FUNCTION "FC_GRP_80_R30" : VOID
TITLE =GROUP =80
{ S7_language := '9(1) Angielski (Stany Zjednoczone)  11.01.2022  09:45:15' }
VERSION : 0.1


VAR_TEMP
  CL : "UDT_CABINET";	//CABINET LOCAL
  CR : "UDT_CABINET";	//CABINET REMOTE
  RelError : BOOL ;	//ERROR RELEASE
  RelErrorCL : BOOL ;	//ERROR RELEASE FROM CABINET LOCAL
  RelErrorCR : BOOL ;	//ERROR RELEASE FROM CABINET REMOTE
  RelControl : BOOL ;	//CONTROL RELEASE
  RelControlCL : BOOL ;	//CONTROL RELEASE FROM CABINET LOCAL
  RelControlCR : BOOL ;	//CONTROL RELEASE FROM CABINET REMOTE
  ErrorConfirm : BOOL ;	//ERROR CONFIRM
  AutoOn : BOOL ;	//AUTOMATIC ON
  AutoOff : BOOL ;	//AUTOMATIC OFF
  RelAuto : BOOL ;	//AUTOMATIC RELEASE
  LAMP_ON : BOOL ;
  Safety_Brn71 : BOOL ;
  Safety_Brn72 : BOOL ;
  TempSetpoint : WORD ;
  Runtime_DI : DINT ;
  Runtime_R : REAL ;
  LS_BURNER_1 : BOOL ;
  LS_BURNER_2 : BOOL ;
END_VAR
BEGIN
NETWORK
TITLE =GLOBAL SIGNALS

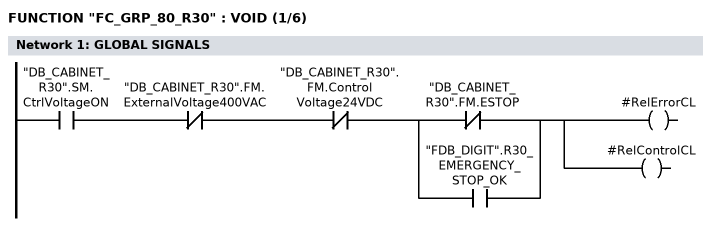
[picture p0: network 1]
      U     "DB_CABINET_R30".SM.CtrlVoltageON;
      UN    "DB_CABINET_R30".FM.ExternalVoltage400VAC;
      UN    "DB_CABINET_R30".FM.ControlVoltage24VDC;
      U(    ;
      ON    "DB_CABINET_R30".FM.ESTOP;
      O     "FDB_DIGIT".R30_EMERGENCY_STOP_OK;
      )     ;
      =     #RelErrorCL;
      =     #RelControlCL;
NETWORK
TITLE =GLOBAL SIGNALS



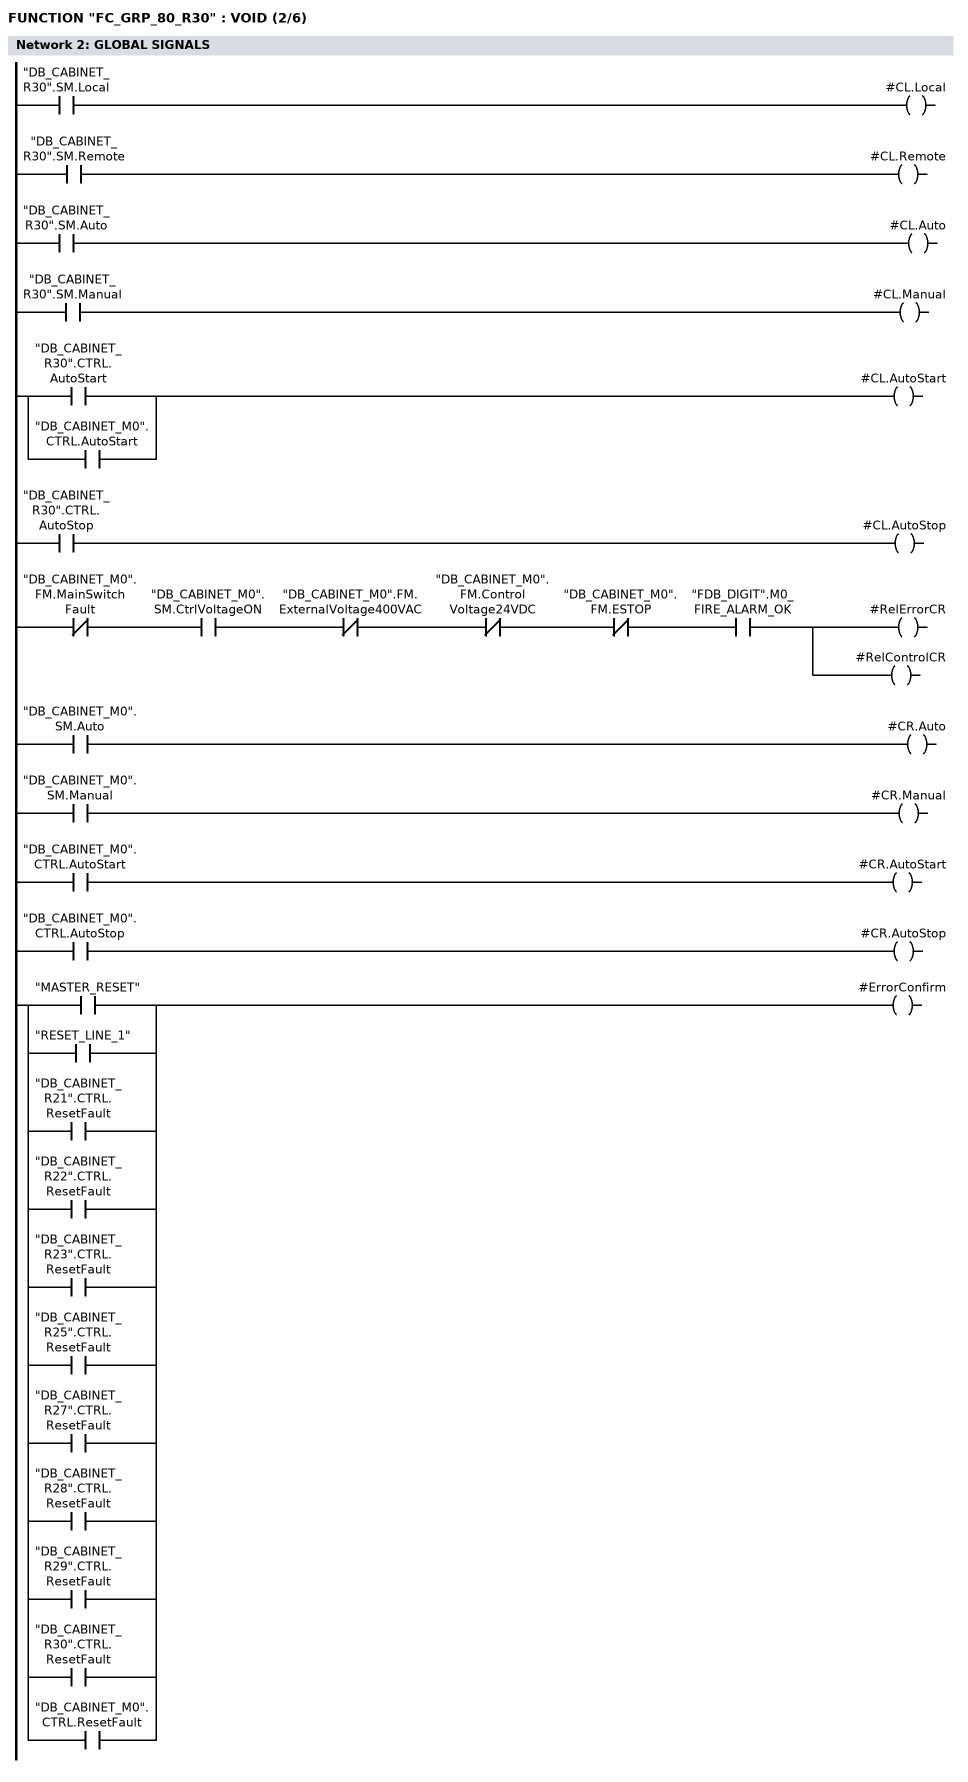
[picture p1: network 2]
      U     "DB_CABINET_R30".SM.Local;
      =     #CL.Local;
      U     "DB_CABINET_R30".SM.Remote;
      =     #CL.Remote;
      U     "DB_CABINET_R30".SM.Auto;
      =     #CL.Auto;
      U     "DB_CABINET_R30".SM.Manual;
      =     #CL.Manual;
      U     "DB_CABINET_R30".CTRL.AutoStart;
      O     "DB_CABINET_M0".CTRL.AutoStart;
      =     #CL.AutoStart;
      U     "DB_CABINET_R30".CTRL.AutoStop;
      =     #CL.AutoStop;


//REMOTE
      UN    "DB_CABINET_M0".FM.MainSwitchFault;
      U     "DB_CABINET_M0".SM.CtrlVoltageON;
      UN    "DB_CABINET_M0".FM.ExternalVoltage400VAC;
      UN    "DB_CABINET_M0".FM.ControlVoltage24VDC;
      UN    "DB_CABINET_M0".FM.ESTOP;
      U     "FDB_DIGIT".M0_FIRE_ALARM_OK;
      =     #RelErrorCR;
      =     #RelControlCR;

      U     "DB_CABINET_M0".SM.Auto;
      =     #CR.Auto;
      U     "DB_CABINET_M0".SM.Manual;
      =     #CR.Manual;
      U     "DB_CABINET_M0".CTRL.AutoStart;
      =     #CR.AutoStart;
      U     "DB_CABINET_M0".CTRL.AutoStop;
      =     #CR.AutoStop;

// Reset Alarms
      U     "MASTER_RESET";
      O     "RESET_LINE_1";
      O     "DB_CABINET_R21".CTRL.ResetFault;
      O     "DB_CABINET_R22".CTRL.ResetFault;
      O     "DB_CABINET_R23".CTRL.ResetFault;
      O     "DB_CABINET_R25".CTRL.ResetFault;
      O     "DB_CABINET_R27".CTRL.ResetFault;
      O     "DB_CABINET_R28".CTRL.ResetFault;
      O     "DB_CABINET_R29".CTRL.ResetFault;
      O     "DB_CABINET_R30".CTRL.ResetFault;
      O     "DB_CABINET_M0".CTRL.ResetFault;
      =     #ErrorConfirm;

NETWORK
TITLE =GLOBAL SIGNALS - GROUP GENERAL ERROR AND WARNING


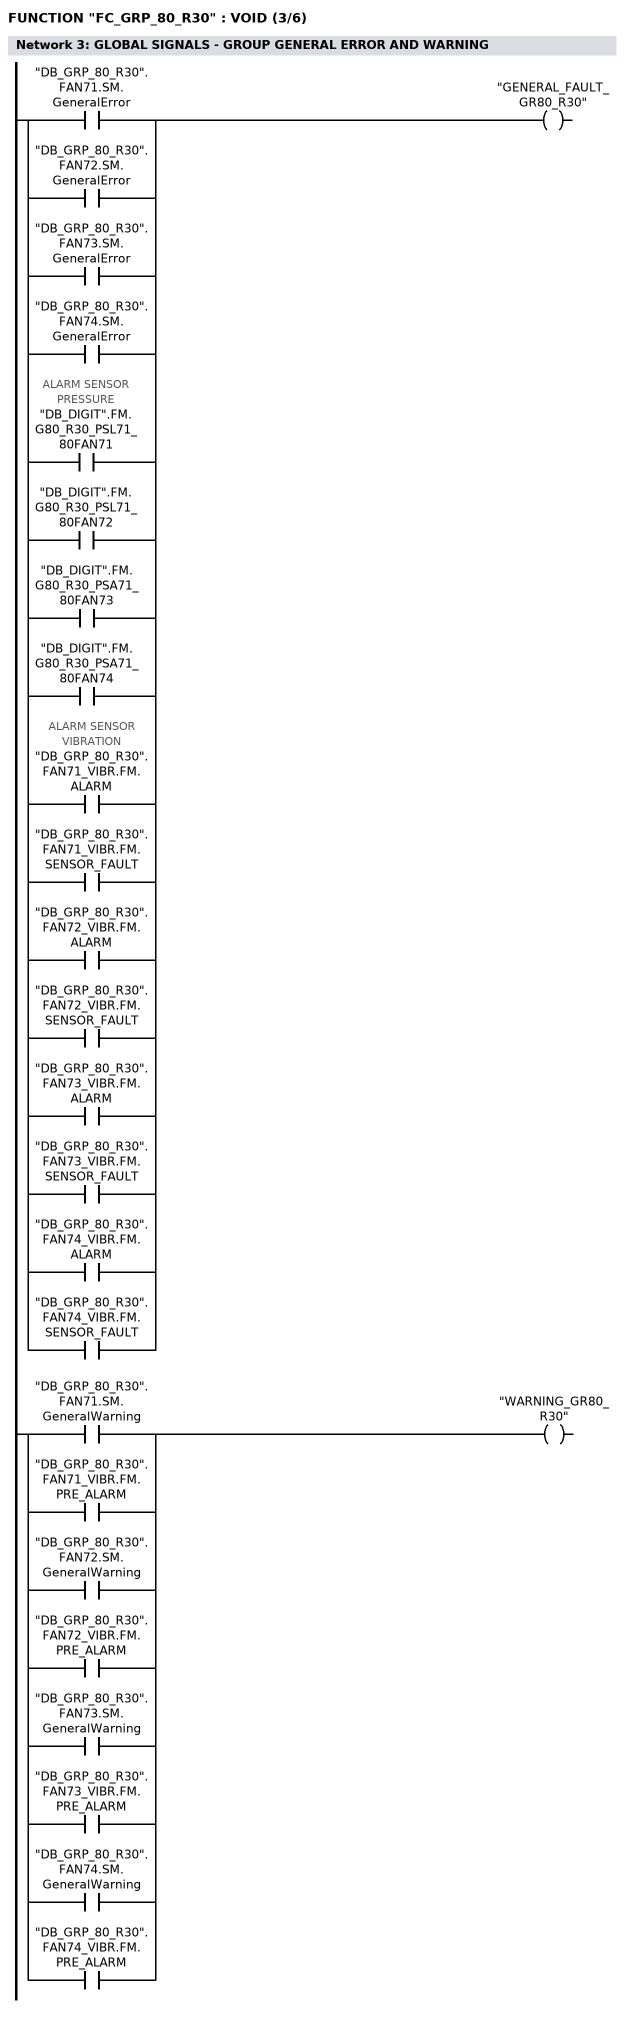
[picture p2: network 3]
      U     "DB_GRP_80_R30".FAN71.SM.GeneralError;
      O     "DB_GRP_80_R30".FAN72.SM.GeneralError;
      O     "DB_GRP_80_R30".FAN73.SM.GeneralError;
      O     "DB_GRP_80_R30".FAN74.SM.GeneralError;

      O     "DB_DIGIT".FM.G80_R30_PSL71_80FAN71; //ALARM SENSOR PRESSURE
      O     "DB_DIGIT".FM.G80_R30_PSL71_80FAN72;
      O     "DB_DIGIT".FM.G80_R30_PSA71_80FAN73;
      O     "DB_DIGIT".FM.G80_R30_PSA71_80FAN74;

      O     "DB_GRP_80_R30".FAN71_VIBR.FM.ALARM; //ALARM SENSOR VIBRATION
      O     "DB_GRP_80_R30".FAN71_VIBR.FM.SENSOR_FAULT;
      O     "DB_GRP_80_R30".FAN72_VIBR.FM.ALARM;
      O     "DB_GRP_80_R30".FAN72_VIBR.FM.SENSOR_FAULT;
      O     "DB_GRP_80_R30".FAN73_VIBR.FM.ALARM;
      O     "DB_GRP_80_R30".FAN73_VIBR.FM.SENSOR_FAULT;
      O     "DB_GRP_80_R30".FAN74_VIBR.FM.ALARM;
      O     "DB_GRP_80_R30".FAN74_VIBR.FM.SENSOR_FAULT;
      =     "GENERAL_FAULT_GR80_R30";

      U     "DB_GRP_80_R30".FAN71.SM.GeneralWarning;
      O     "DB_GRP_80_R30".FAN71_VIBR.FM.PRE_ALARM;
      O     "DB_GRP_80_R30".FAN72.SM.GeneralWarning;
      O     "DB_GRP_80_R30".FAN72_VIBR.FM.PRE_ALARM;
      O     "DB_GRP_80_R30".FAN73.SM.GeneralWarning;
      O     "DB_GRP_80_R30".FAN73_VIBR.FM.PRE_ALARM;
      O     "DB_GRP_80_R30".FAN74.SM.GeneralWarning;
      O     "DB_GRP_80_R30".FAN74_VIBR.FM.PRE_ALARM;
      =     "WARNING_GR80_R30";

NETWORK
TITLE =



NETWORK
TITLE =GENERAL ERROR RELEASE

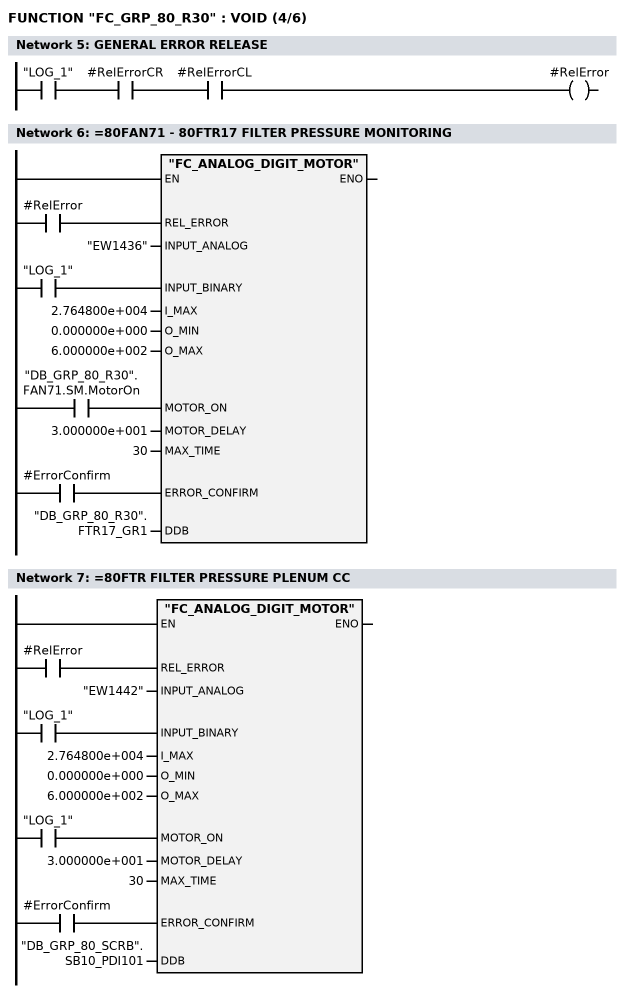
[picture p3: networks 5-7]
      U     "LOG_1";
      U     #RelErrorCR;
      U     #RelErrorCL;
      =     #RelError;
NETWORK
TITLE ==80FAN71 - 80FTR17 FILTER PRESSURE MONITORING

      U     #RelError;
      =     L     17.0;
      BLD   103;
      U     "LOG_1";
      =     L     17.1;
      BLD   103;
      U     "DB_GRP_80_R30".FAN71.SM.MotorOn;
      =     L     17.2;
      BLD   103;
      U     #ErrorConfirm;
      =     L     17.3;
      BLD   103;
      CALL "FC_ANALOG_DIGIT_MOTOR" (
           REL_ERROR                := L     17.0,
           INPUT_ANALOG             := "EW1436",
           INPUT_BINARY             := L     17.1,
           I_MAX                    := 2.764800e+004,
           O_MIN                    := 0.000000e+000,
           O_MAX                    := 6.000000e+002,
           MOTOR_ON                 := L     17.2,
           MOTOR_DELAY              := 3.000000e+001,
           MAX_TIME                 := 30,
           ERROR_CONFIRM            := L     17.3,
           DDB                      := "DB_GRP_80_R30".FTR17_GR1);
      NOP   0;
NETWORK
TITLE ==80FTR FILTER PRESSURE PLENUM CC

      U     #RelError;
      =     L     17.0;
      BLD   103;
      U     "LOG_1";
      =     L     17.1;
      BLD   103;
      U     "LOG_1";
      =     L     17.2;
      BLD   103;
      U     #ErrorConfirm;
      =     L     17.3;
      BLD   103;
      CALL "FC_ANALOG_DIGIT_MOTOR" (
           REL_ERROR                := L     17.0,
           INPUT_ANALOG             := "EW1442",
           INPUT_BINARY             := L     17.1,
           I_MAX                    := 2.764800e+004,
           O_MIN                    := 0.000000e+000,
           O_MAX                    := 6.000000e+002,
           MOTOR_ON                 := L     17.2,
           MOTOR_DELAY              := 3.000000e+001,
           MAX_TIME                 := 30,
           ERROR_CONFIRM            := L     17.3,
           DDB                      := "DB_GRP_80_SCRB".SB10_PDI101);
      NOP   0;
NETWORK
TITLE ==80FAN72 - 80FTR27 FILTER PRESSURE MONITORING

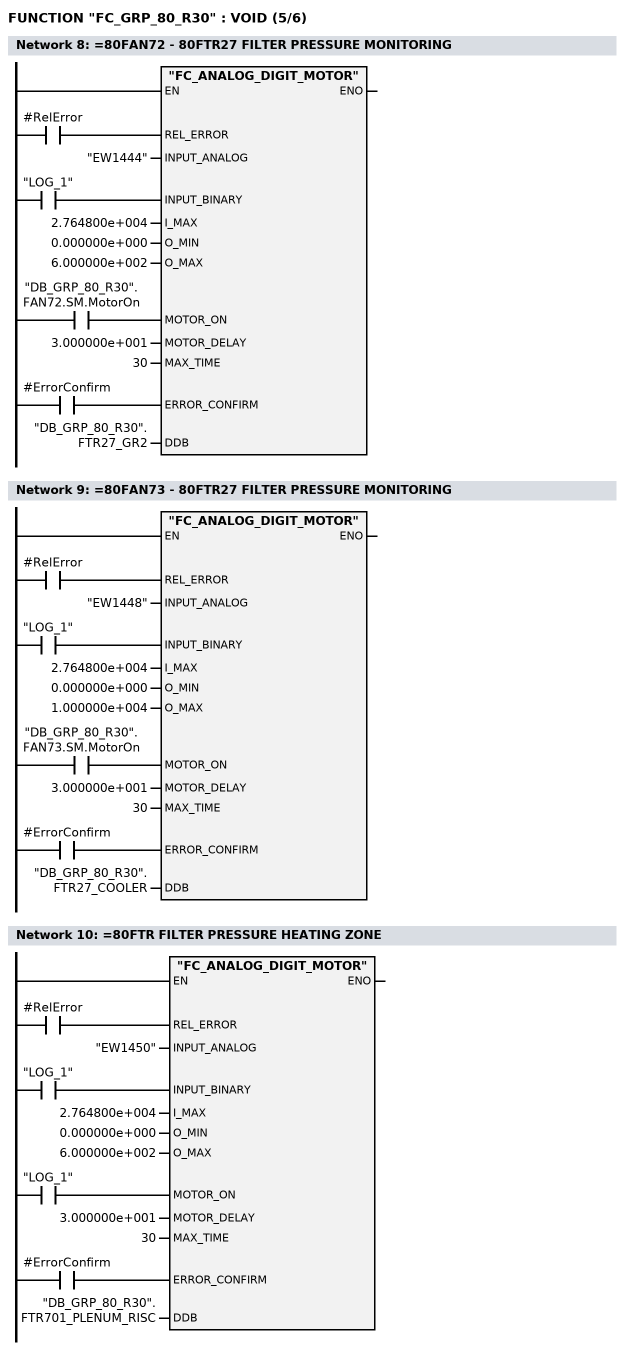
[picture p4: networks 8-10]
      U     #RelError;
      =     L     17.0;
      BLD   103;
      U     "LOG_1";
      =     L     17.1;
      BLD   103;
      U     "DB_GRP_80_R30".FAN72.SM.MotorOn;
      =     L     17.2;
      BLD   103;
      U     #ErrorConfirm;
      =     L     17.3;
      BLD   103;
      CALL "FC_ANALOG_DIGIT_MOTOR" (
           REL_ERROR                := L     17.0,
           INPUT_ANALOG             := "EW1444",
           INPUT_BINARY             := L     17.1,
           I_MAX                    := 2.764800e+004,
           O_MIN                    := 0.000000e+000,
           O_MAX                    := 6.000000e+002,
           MOTOR_ON                 := L     17.2,
           MOTOR_DELAY              := 3.000000e+001,
           MAX_TIME                 := 30,
           ERROR_CONFIRM            := L     17.3,
           DDB                      := "DB_GRP_80_R30".FTR27_GR2);
      NOP   0;
NETWORK
TITLE ==80FAN73 - 80FTR27 FILTER PRESSURE MONITORING

      U     #RelError;
      =     L     17.0;
      BLD   103;
      U     "LOG_1";
      =     L     17.1;
      BLD   103;
      U     "DB_GRP_80_R30".FAN73.SM.MotorOn;
      =     L     17.2;
      BLD   103;
      U     #ErrorConfirm;
      =     L     17.3;
      BLD   103;
      CALL "FC_ANALOG_DIGIT_MOTOR" (
           REL_ERROR                := L     17.0,
           INPUT_ANALOG             := "EW1448",
           INPUT_BINARY             := L     17.1,
           I_MAX                    := 2.764800e+004,
           O_MIN                    := 0.000000e+000,
           O_MAX                    := 1.000000e+004,
           MOTOR_ON                 := L     17.2,
           MOTOR_DELAY              := 3.000000e+001,
           MAX_TIME                 := 30,
           ERROR_CONFIRM            := L     17.3,
           DDB                      := "DB_GRP_80_R30".FTR27_COOLER);
      NOP   0;
NETWORK
TITLE ==80FTR FILTER PRESSURE HEATING ZONE

      U     #RelError;
      =     L     17.0;
      BLD   103;
      U     "LOG_1";
      =     L     17.1;
      BLD   103;
      U     "LOG_1";
      =     L     17.2;
      BLD   103;
      U     #ErrorConfirm;
      =     L     17.3;
      BLD   103;
      CALL "FC_ANALOG_DIGIT_MOTOR" (
           REL_ERROR                := L     17.0,
           INPUT_ANALOG             := "EW1450",
           INPUT_BINARY             := L     17.1,
           I_MAX                    := 2.764800e+004,
           O_MIN                    := 0.000000e+000,
           O_MAX                    := 6.000000e+002,
           MOTOR_ON                 := L     17.2,
           MOTOR_DELAY              := 3.000000e+001,
           MAX_TIME                 := 30,
           ERROR_CONFIRM            := L     17.3,
           DDB                      := "DB_GRP_80_R30".FTR701_PLENUM_RISC);
      NOP   0;
NETWORK
TITLE ==80FTR FILTER PRESSURE COOLING ZONE

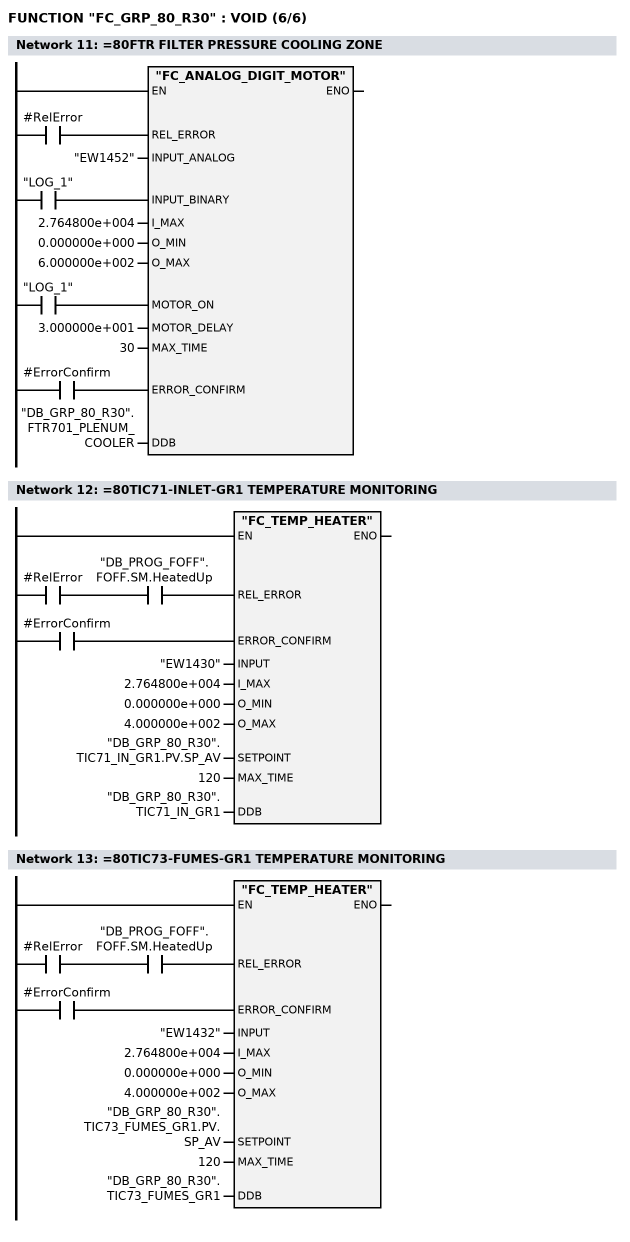
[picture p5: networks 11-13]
      U     #RelError;
      =     L     17.0;
      BLD   103;
      U     "LOG_1";
      =     L     17.1;
      BLD   103;
      U     "LOG_1";
      =     L     17.2;
      BLD   103;
      U     #ErrorConfirm;
      =     L     17.3;
      BLD   103;
      CALL "FC_ANALOG_DIGIT_MOTOR" (
           REL_ERROR                := L     17.0,
           INPUT_ANALOG             := "EW1452",
           INPUT_BINARY             := L     17.1,
           I_MAX                    := 2.764800e+004,
           O_MIN                    := 0.000000e+000,
           O_MAX                    := 6.000000e+002,
           MOTOR_ON                 := L     17.2,
           MOTOR_DELAY              := 3.000000e+001,
           MAX_TIME                 := 30,
           ERROR_CONFIRM            := L     17.3,
           DDB                      := "DB_GRP_80_R30".FTR701_PLENUM_COOLER);
      NOP   0;
NETWORK
TITLE ==80TIC71-INLET-GR1 TEMPERATURE MONITORING

      U     #RelError;
      U     "DB_PROG_FOFF".FOFF.SM.HeatedUp;
      =     L     17.0;
      BLD   103;
      U     #ErrorConfirm;
      =     L     17.1;
      BLD   103;
      CALL "FC_TEMP_HEATER" (
           REL_ERROR                := L     17.0,
           ERROR_CONFIRM            := L     17.1,
           INPUT                    := "EW1430",
           I_MAX                    := 2.764800e+004,
           O_MIN                    := 0.000000e+000,
           O_MAX                    := 4.000000e+002,
           SETPOINT                 := "DB_GRP_80_R30".TIC71_IN_GR1.PV.SP_AV,
           MAX_TIME                 := 120,
           DDB                      := "DB_GRP_80_R30".TIC71_IN_GR1);
      NOP   0;
NETWORK
TITLE ==80TIC73-FUMES-GR1 TEMPERATURE MONITORING

      U     #RelError;
      U     "DB_PROG_FOFF".FOFF.SM.HeatedUp;
      =     L     17.0;
      BLD   103;
      U     #ErrorConfirm;
      =     L     17.1;
      BLD   103;
      CALL "FC_TEMP_HEATER" (
           REL_ERROR                := L     17.0,
           ERROR_CONFIRM            := L     17.1,
           INPUT                    := "EW1432",
           I_MAX                    := 2.764800e+004,
           O_MIN                    := 0.000000e+000,
           O_MAX                    := 4.000000e+002,
           SETPOINT                 := "DB_GRP_80_R30".TIC73_FUMES_GR1.PV.SP_AV,
           MAX_TIME                 := 120,
           DDB                      := "DB_GRP_80_R30".TIC73_FUMES_GR1);
      NOP   0;
NETWORK
TITLE ==80TIC71-RETURN-GR1 TEMPERATURE MONITORING


      L     "EW1454";
      L     0;
      >=I   ;
      SPB   M014;
      L     0.000000e+000;
      SPA   M015;
M014: L     "EW1454";
      ITD   ;
      DTR   ;
      L     1.000000e+001;
      /R    ;
M015: T     "DB_GRP_80_R30".TIC71_RET_GR1.PV.AV;

NETWORK
TITLE ==80TIC71-INLET-GR2 TEMPERATURE MONITORING

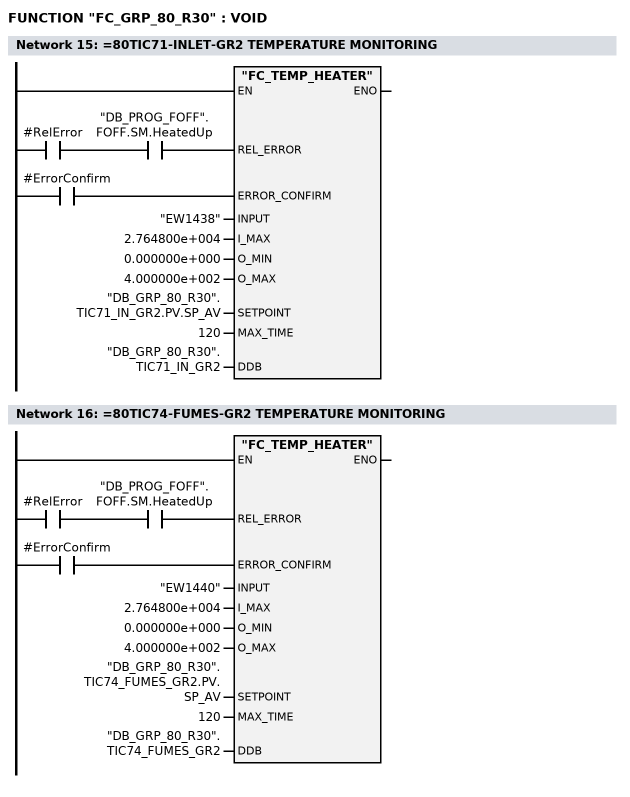
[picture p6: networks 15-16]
      U     #RelError;
      U     "DB_PROG_FOFF".FOFF.SM.HeatedUp;
      =     L     17.0;
      BLD   103;
      U     #ErrorConfirm;
      =     L     17.1;
      BLD   103;
      CALL "FC_TEMP_HEATER" (
           REL_ERROR                := L     17.0,
           ERROR_CONFIRM            := L     17.1,
           INPUT                    := "EW1438",
           I_MAX                    := 2.764800e+004,
           O_MIN                    := 0.000000e+000,
           O_MAX                    := 4.000000e+002,
           SETPOINT                 := "DB_GRP_80_R30".TIC71_IN_GR2.PV.SP_AV,
           MAX_TIME                 := 120,
           DDB                      := "DB_GRP_80_R30".TIC71_IN_GR2);
      NOP   0;
NETWORK
TITLE ==80TIC74-FUMES-GR2 TEMPERATURE MONITORING

      U     #RelError;
      U     "DB_PROG_FOFF".FOFF.SM.HeatedUp;
      =     L     17.0;
      BLD   103;
      U     #ErrorConfirm;
      =     L     17.1;
      BLD   103;
      CALL "FC_TEMP_HEATER" (
           REL_ERROR                := L     17.0,
           ERROR_CONFIRM            := L     17.1,
           INPUT                    := "EW1440",
           I_MAX                    := 2.764800e+004,
           O_MIN                    := 0.000000e+000,
           O_MAX                    := 4.000000e+002,
           SETPOINT                 := "DB_GRP_80_R30".TIC74_FUMES_GR2.PV.SP_AV,
           MAX_TIME                 := 120,
           DDB                      := "DB_GRP_80_R30".TIC74_FUMES_GR2);
      NOP   0;
NETWORK
TITLE ==80TIC72-RETURN-GR2 TEMPERATURE MONITORING


      L     "EW1456";
      L     0;
      >=I   ;
      SPB   M016;
      L     0.000000e+000;
      SPA   M017;
M016: L     "EW1456";
      ITD   ;
      DTR   ;
      L     1.000000e+001;
      /R    ;
M017: T     "DB_GRP_80_R30".TIC72_RET_GR2.PV.AV;

NETWORK
TITLE =



NETWORK
TITLE ==80TIC75-COOLING TEMPERATURE MONITORING

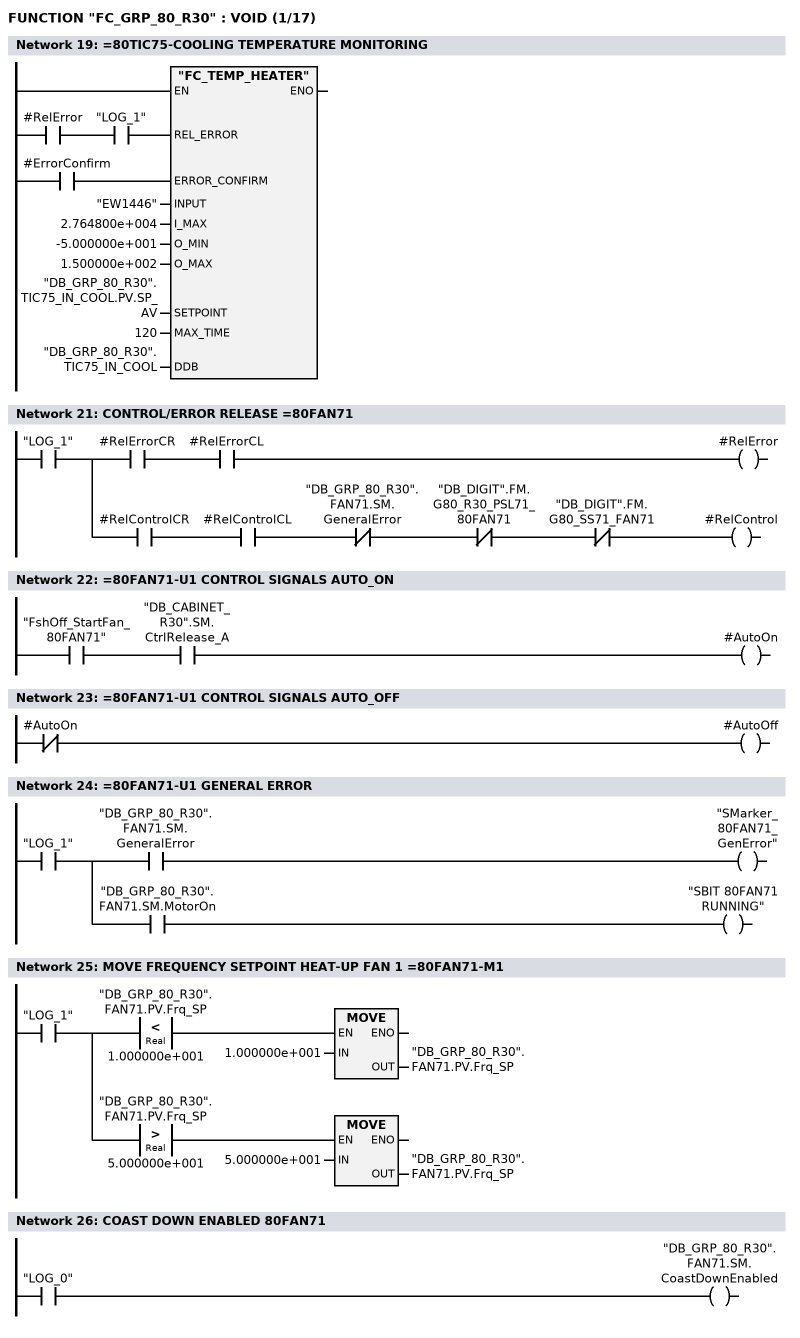
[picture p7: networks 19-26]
      U     #RelError;
      U     "LOG_1";
      =     L     17.0;
      BLD   103;
      U     #ErrorConfirm;
      =     L     17.1;
      BLD   103;
      CALL "FC_TEMP_HEATER" (
           REL_ERROR                := L     17.0,
           ERROR_CONFIRM            := L     17.1,
           INPUT                    := "EW1446",
           I_MAX                    := 2.764800e+004,
           O_MIN                    := -5.000000e+001,
           O_MAX                    := 1.500000e+002,
           SETPOINT                 := "DB_GRP_80_R30".TIC75_IN_COOL.PV.SP_AV,
           MAX_TIME                 := 120,
           DDB                      := "DB_GRP_80_R30".TIC75_IN_COOL);
      NOP   0;
NETWORK
TITLE =



NETWORK
TITLE =CONTROL/ERROR RELEASE =80FAN71

      U     "LOG_1";
      =     L     17.0;
      U     L     17.0;
      U     #RelErrorCR;
      U     #RelErrorCL;
      =     #RelError;
      U     L     17.0;
      U     #RelControlCR;
      U     #RelControlCL;
      UN    "DB_GRP_80_R30".FAN71.SM.GeneralError;
      UN    "DB_DIGIT".FM.G80_R30_PSL71_80FAN71;
      UN    "DB_DIGIT".FM.G80_SS71_FAN71;
      =     #RelControl;
NETWORK
TITLE ==80FAN71-U1 CONTROL SIGNALS AUTO_ON

      U     "FshOff_StartFan_80FAN71";
      U     "DB_CABINET_R30".SM.CtrlRelease_A;
      =     #AutoOn;
NETWORK
TITLE ==80FAN71-U1 CONTROL SIGNALS AUTO_OFF

      UN    #AutoOn;
      =     #AutoOff;
NETWORK
TITLE ==80FAN71-U1 GENERAL ERROR

      U     "LOG_1";
      =     L     17.0;
      U     L     17.0;
      U     "DB_GRP_80_R30".FAN71.SM.GeneralError;
      =     "SMarker_80FAN71_GenError";
      U     L     17.0;
      U     "DB_GRP_80_R30".FAN71.SM.MotorOn;
      =     "SBIT 80FAN71 RUNNING";
NETWORK
TITLE =MOVE FREQUENCY SETPOINT HEAT-UP FAN 1 =80FAN71-M1

      U     "LOG_1";
      =     L     17.0;
      U     L     17.0;
      U(    ;
      L     "DB_GRP_80_R30".FAN71.PV.Frq_SP;
      L     1.000000e+001;
      <R    ;
      )     ;
      SPBNB _001;
      L     1.000000e+001;
      T     "DB_GRP_80_R30".FAN71.PV.Frq_SP;
_001: NOP   0;
      U     L     17.0;
      U(    ;
      L     "DB_GRP_80_R30".FAN71.PV.Frq_SP;
      L     5.000000e+001;
      >R    ;
      )     ;
      SPBNB _002;
      L     5.000000e+001;
      T     "DB_GRP_80_R30".FAN71.PV.Frq_SP;
_002: NOP   0;
NETWORK
TITLE =COAST DOWN ENABLED 80FAN71

      U     "LOG_0";
      =     "DB_GRP_80_R30".FAN71.SM.CoastDownEnabled;
NETWORK
TITLE ==80FAN71-U1 HEAT-UP FAN

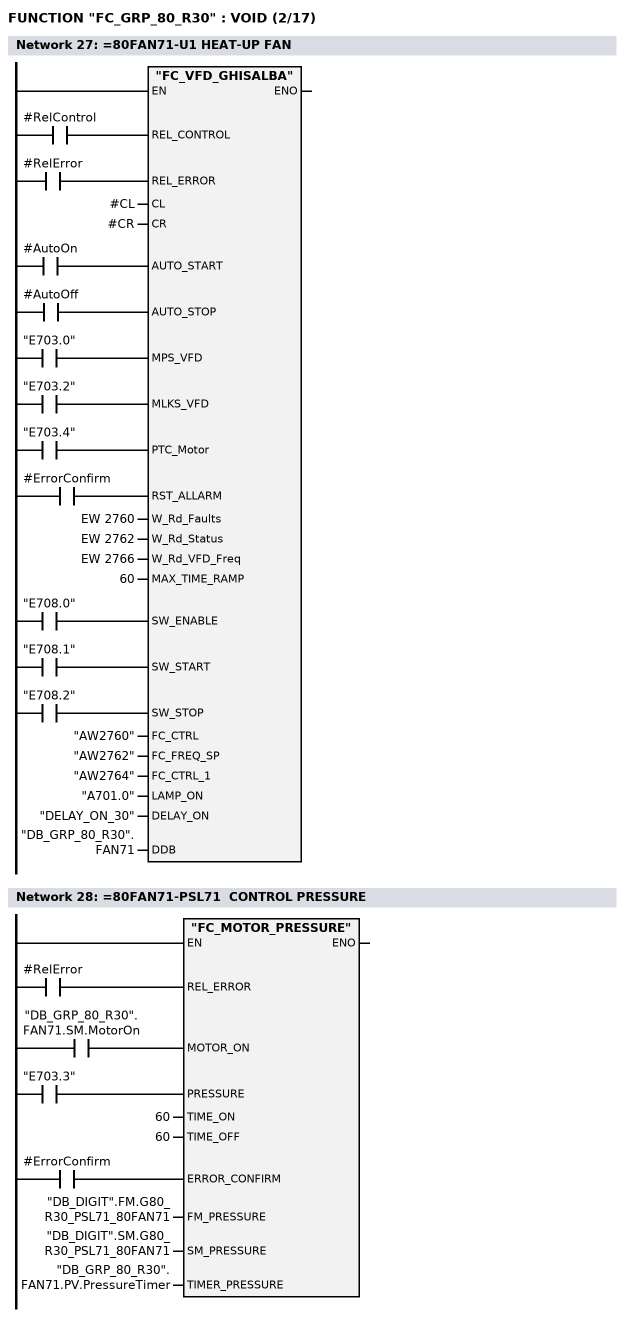
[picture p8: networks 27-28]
      U     #RelControl;
      =     L     17.0;
      BLD   103;
      U     #RelError;
      =     L     17.1;
      BLD   103;
      U     #AutoOn;
      =     L     17.2;
      BLD   103;
      U     #AutoOff;
      =     L     17.3;
      BLD   103;
      U     "E703.0";
      =     L     17.4;
      BLD   103;
      U     "E703.2";
      =     L     17.5;
      BLD   103;
      U     "E703.4";
      =     L     17.6;
      BLD   103;
      U     #ErrorConfirm;
      =     L     17.7;
      BLD   103;
      U     "E708.0";
      =     L     18.0;
      BLD   103;
      U     "E708.1";
      =     L     18.1;
      BLD   103;
      U     "E708.2";
      =     L     18.2;
      BLD   103;
      CALL "FC_VFD_GHISALBA" (
           REL_CONTROL              := L     17.0,
           REL_ERROR                := L     17.1,
           CL                       := #CL,
           CR                       := #CR,
           AUTO_START               := L     17.2,
           AUTO_STOP                := L     17.3,
           MPS_VFD                  := L     17.4,
           MLKS_VFD                 := L     17.5,
           PTC_Motor                := L     17.6,
           RST_ALLARM               := L     17.7,
           W_Rd_Faults              := EW  2760,
           W_Rd_Status              := EW  2762,
           W_Rd_VFD_Freq            := EW  2766,
           MAX_TIME_RAMP            := 60,
           SW_ENABLE                := L     18.0,
           SW_START                 := L     18.1,
           SW_STOP                  := L     18.2,
           FC_CTRL                  := "AW2760",
           FC_FREQ_SP               := "AW2762",
           FC_CTRL_1                := "AW2764",
           LAMP_ON                  := "A701.0",
           DELAY_ON                 := "DELAY_ON_30",
           DDB                      := "DB_GRP_80_R30".FAN71);
      NOP   0;
NETWORK
TITLE ==80FAN71-PSL71  CONTROL PRESSURE

      U     #RelError;
      =     L     17.0;
      BLD   103;
      U     "DB_GRP_80_R30".FAN71.SM.MotorOn;
      =     L     17.1;
      BLD   103;
      U     "E703.3";
      =     L     17.2;
      BLD   103;
      U     #ErrorConfirm;
      =     L     17.3;
      BLD   103;
      CALL "FC_MOTOR_PRESSURE" (
           REL_ERROR                := L     17.0,
           MOTOR_ON                 := L     17.1,
           PRESSURE                 := L     17.2,
           TIME_ON                  := 60,
           TIME_OFF                 := 60,
           ERROR_CONFIRM            := L     17.3,
           FM_PRESSURE              := "DB_DIGIT".FM.G80_R30_PSL71_80FAN71,
           SM_PRESSURE              := "DB_DIGIT".SM.G80_R30_PSL71_80FAN71,
           TIMER_PRESSURE           := "DB_GRP_80_R30".FAN71.PV.PressureTimer);
      NOP   0;
NETWORK
TITLE =VIBRATION SENSOR =80FAN71

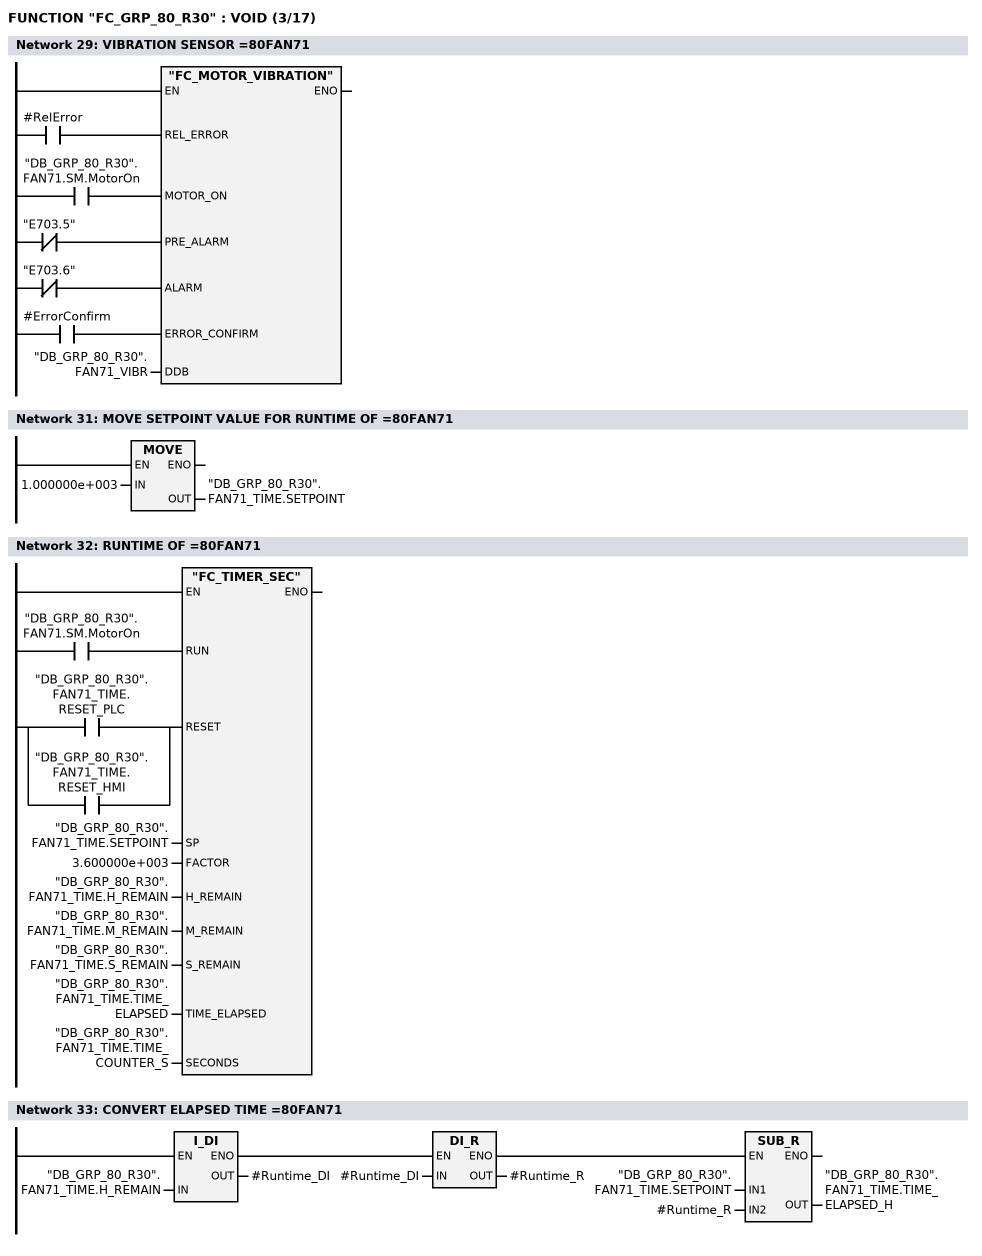
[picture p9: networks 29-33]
      U     #RelError;
      =     L     17.0;
      BLD   103;
      U     "DB_GRP_80_R30".FAN71.SM.MotorOn;
      =     L     17.1;
      BLD   103;
      UN    "E703.5";
      =     L     17.2;
      BLD   103;
      UN    "E703.6";
      =     L     17.3;
      BLD   103;
      U     #ErrorConfirm;
      =     L     17.4;
      BLD   103;
      CALL "FC_MOTOR_VIBRATION" (
           REL_ERROR                := L     17.0,
           MOTOR_ON                 := L     17.1,
           PRE_ALARM                := L     17.2,
           ALARM                    := L     17.3,
           ERROR_CONFIRM            := L     17.4,
           DDB                      := "DB_GRP_80_R30".FAN71_VIBR);
      NOP   0;
NETWORK
TITLE =****** RUNTIME METER ********



NETWORK
TITLE =MOVE SETPOINT VALUE FOR RUNTIME OF =80FAN71

      L     1.000000e+003;
      T     "DB_GRP_80_R30".FAN71_TIME.SETPOINT;
      NOP   0;
NETWORK
TITLE =RUNTIME OF =80FAN71

      U     "DB_GRP_80_R30".FAN71.SM.MotorOn;
      =     L     17.0;
      BLD   103;
      U(    ;
      O     "DB_GRP_80_R30".FAN71_TIME.RESET_PLC;
      O     "DB_GRP_80_R30".FAN71_TIME.RESET_HMI;
      )     ;
      =     L     17.1;
      BLD   103;
      CALL "FC_TIMER_SEC" (
           RUN                      := L     17.0,
           RESET                    := L     17.1,
           SP                       := "DB_GRP_80_R30".FAN71_TIME.SETPOINT,
           FACTOR                   := 3.600000e+003,
           H_REMAIN                 := "DB_GRP_80_R30".FAN71_TIME.H_REMAIN,
           M_REMAIN                 := "DB_GRP_80_R30".FAN71_TIME.M_REMAIN,
           S_REMAIN                 := "DB_GRP_80_R30".FAN71_TIME.S_REMAIN,
           TIME_ELAPSED             := "DB_GRP_80_R30".FAN71_TIME.TIME_ELAPSED,
           SECONDS                  := "DB_GRP_80_R30".FAN71_TIME.TIME_COUNTER_S);
      NOP   0;
NETWORK
TITLE =CONVERT ELAPSED TIME =80FAN71

      U(    ;
      U(    ;
      L     "DB_GRP_80_R30".FAN71_TIME.H_REMAIN;
      ITD   ;
      T     #Runtime_DI;
      SET   ;
      SAVE  ;
      CLR   ;
      U     BIE;
      )     ;
      SPBNB _003;
      L     #Runtime_DI;
      DTR   ;
      T     #Runtime_R;
      SET   ;
      SAVE  ;
      CLR   ;
_003: U     BIE;
      )     ;
      SPBNB _004;
      L     "DB_GRP_80_R30".FAN71_TIME.SETPOINT;
      L     #Runtime_R;
      -R    ;
      T     "DB_GRP_80_R30".FAN71_TIME.TIME_ELAPSED_H;
_004: NOP   0;
NETWORK
TITLE =



NETWORK
TITLE =CONTROL/ERROR RELEASE =80FAN72

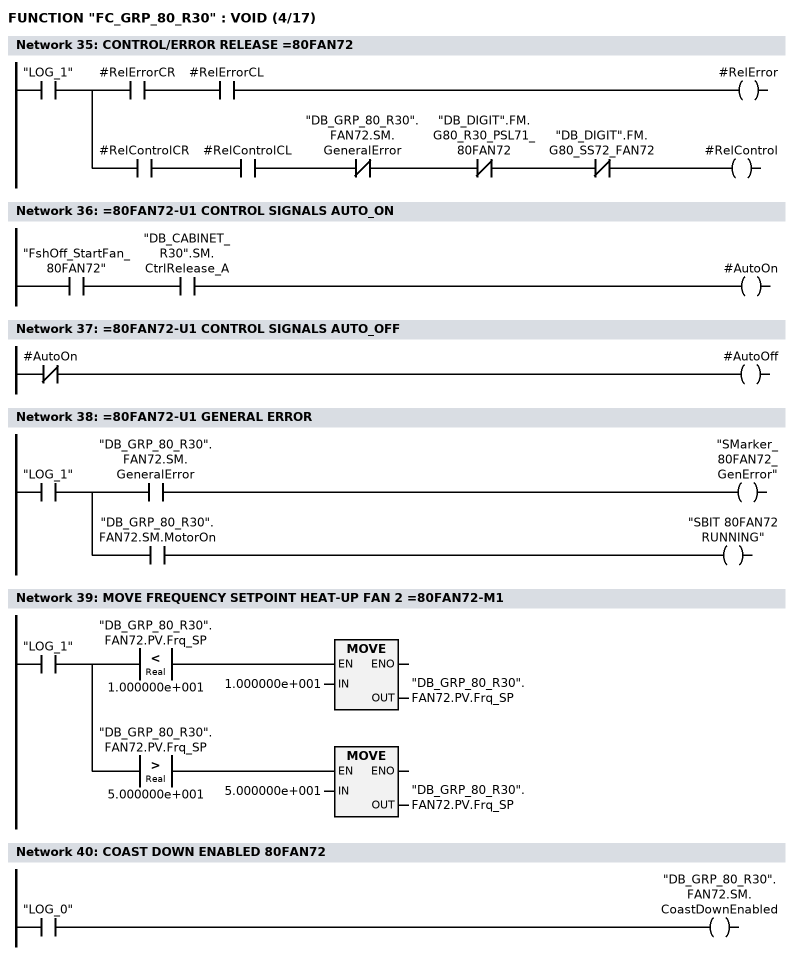
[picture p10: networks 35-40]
      U     "LOG_1";
      =     L     17.0;
      U     L     17.0;
      U     #RelErrorCR;
      U     #RelErrorCL;
      =     #RelError;
      U     L     17.0;
      U     #RelControlCR;
      U     #RelControlCL;
      UN    "DB_GRP_80_R30".FAN72.SM.GeneralError;
      UN    "DB_DIGIT".FM.G80_R30_PSL71_80FAN72;
      UN    "DB_DIGIT".FM.G80_SS72_FAN72;
      =     #RelControl;
NETWORK
TITLE ==80FAN72-U1 CONTROL SIGNALS AUTO_ON

      U     "FshOff_StartFan_80FAN72";
      U     "DB_CABINET_R30".SM.CtrlRelease_A;
      =     #AutoOn;
NETWORK
TITLE ==80FAN72-U1 CONTROL SIGNALS AUTO_OFF

      UN    #AutoOn;
      =     #AutoOff;
NETWORK
TITLE ==80FAN72-U1 GENERAL ERROR

      U     "LOG_1";
      =     L     17.0;
      U     L     17.0;
      U     "DB_GRP_80_R30".FAN72.SM.GeneralError;
      =     "SMarker_80FAN72_GenError";
      U     L     17.0;
      U     "DB_GRP_80_R30".FAN72.SM.MotorOn;
      =     "SBIT 80FAN72 RUNNING";
NETWORK
TITLE =MOVE FREQUENCY SETPOINT HEAT-UP FAN 2 =80FAN72-M1

      U     "LOG_1";
      =     L     17.0;
      U     L     17.0;
      U(    ;
      L     "DB_GRP_80_R30".FAN72.PV.Frq_SP;
      L     1.000000e+001;
      <R    ;
      )     ;
      SPBNB _005;
      L     1.000000e+001;
      T     "DB_GRP_80_R30".FAN72.PV.Frq_SP;
_005: NOP   0;
      U     L     17.0;
      U(    ;
      L     "DB_GRP_80_R30".FAN72.PV.Frq_SP;
      L     5.000000e+001;
      >R    ;
      )     ;
      SPBNB _006;
      L     5.000000e+001;
      T     "DB_GRP_80_R30".FAN72.PV.Frq_SP;
_006: NOP   0;
NETWORK
TITLE =COAST DOWN ENABLED 80FAN72

      U     "LOG_0";
      =     "DB_GRP_80_R30".FAN72.SM.CoastDownEnabled;
NETWORK
TITLE ==80FAN72-U1 HEATING GROUP AIR FAN 2

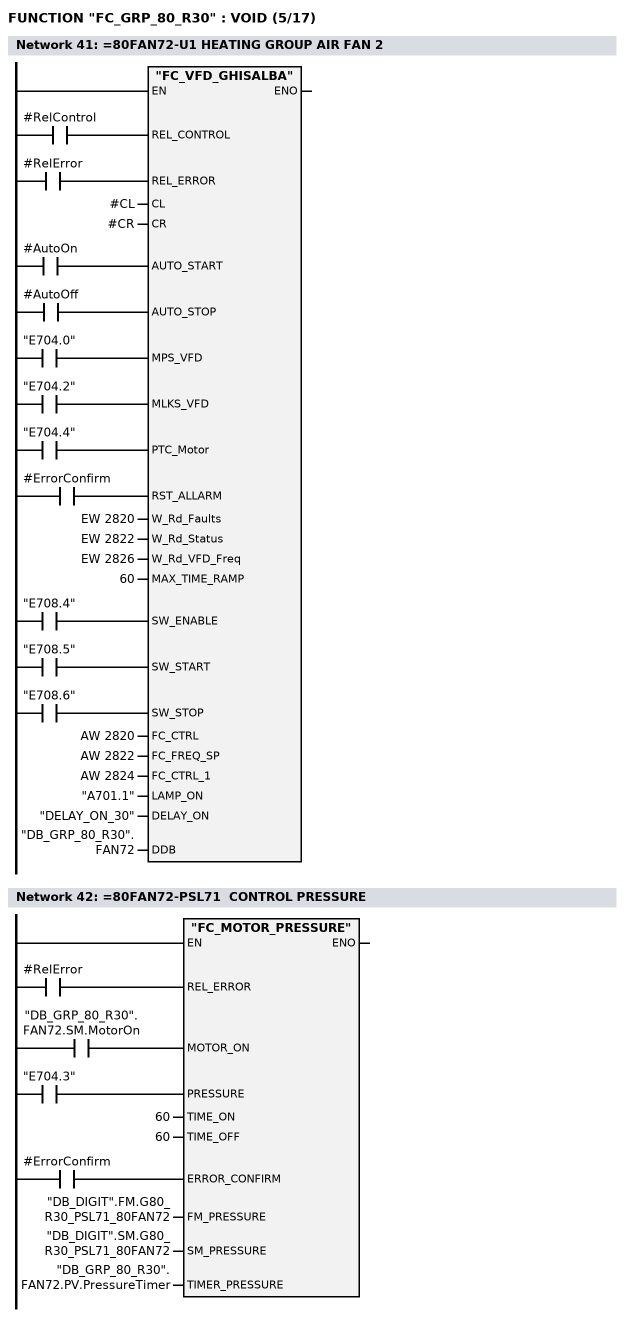
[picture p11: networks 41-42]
      U     #RelControl;
      =     L     17.0;
      BLD   103;
      U     #RelError;
      =     L     17.1;
      BLD   103;
      U     #AutoOn;
      =     L     17.2;
      BLD   103;
      U     #AutoOff;
      =     L     17.3;
      BLD   103;
      U     "E704.0";
      =     L     17.4;
      BLD   103;
      U     "E704.2";
      =     L     17.5;
      BLD   103;
      U     "E704.4";
      =     L     17.6;
      BLD   103;
      U     #ErrorConfirm;
      =     L     17.7;
      BLD   103;
      U     "E708.4";
      =     L     18.0;
      BLD   103;
      U     "E708.5";
      =     L     18.1;
      BLD   103;
      U     "E708.6";
      =     L     18.2;
      BLD   103;
      CALL "FC_VFD_GHISALBA" (
           REL_CONTROL              := L     17.0,
           REL_ERROR                := L     17.1,
           CL                       := #CL,
           CR                       := #CR,
           AUTO_START               := L     17.2,
           AUTO_STOP                := L     17.3,
           MPS_VFD                  := L     17.4,
           MLKS_VFD                 := L     17.5,
           PTC_Motor                := L     17.6,
           RST_ALLARM               := L     17.7,
           W_Rd_Faults              := EW  2820,
           W_Rd_Status              := EW  2822,
           W_Rd_VFD_Freq            := EW  2826,
           MAX_TIME_RAMP            := 60,
           SW_ENABLE                := L     18.0,
           SW_START                 := L     18.1,
           SW_STOP                  := L     18.2,
           FC_CTRL                  := AW  2820,
           FC_FREQ_SP               := AW  2822,
           FC_CTRL_1                := AW  2824,
           LAMP_ON                  := "A701.1",
           DELAY_ON                 := "DELAY_ON_30",
           DDB                      := "DB_GRP_80_R30".FAN72);
      NOP   0;
NETWORK
TITLE ==80FAN72-PSL71  CONTROL PRESSURE

      U     #RelError;
      =     L     17.0;
      BLD   103;
      U     "DB_GRP_80_R30".FAN72.SM.MotorOn;
      =     L     17.1;
      BLD   103;
      U     "E704.3";
      =     L     17.2;
      BLD   103;
      U     #ErrorConfirm;
      =     L     17.3;
      BLD   103;
      CALL "FC_MOTOR_PRESSURE" (
           REL_ERROR                := L     17.0,
           MOTOR_ON                 := L     17.1,
           PRESSURE                 := L     17.2,
           TIME_ON                  := 60,
           TIME_OFF                 := 60,
           ERROR_CONFIRM            := L     17.3,
           FM_PRESSURE              := "DB_DIGIT".FM.G80_R30_PSL71_80FAN72,
           SM_PRESSURE              := "DB_DIGIT".SM.G80_R30_PSL71_80FAN72,
           TIMER_PRESSURE           := "DB_GRP_80_R30".FAN72.PV.PressureTimer);
      NOP   0;
NETWORK
TITLE =VIBRATION SENSOR

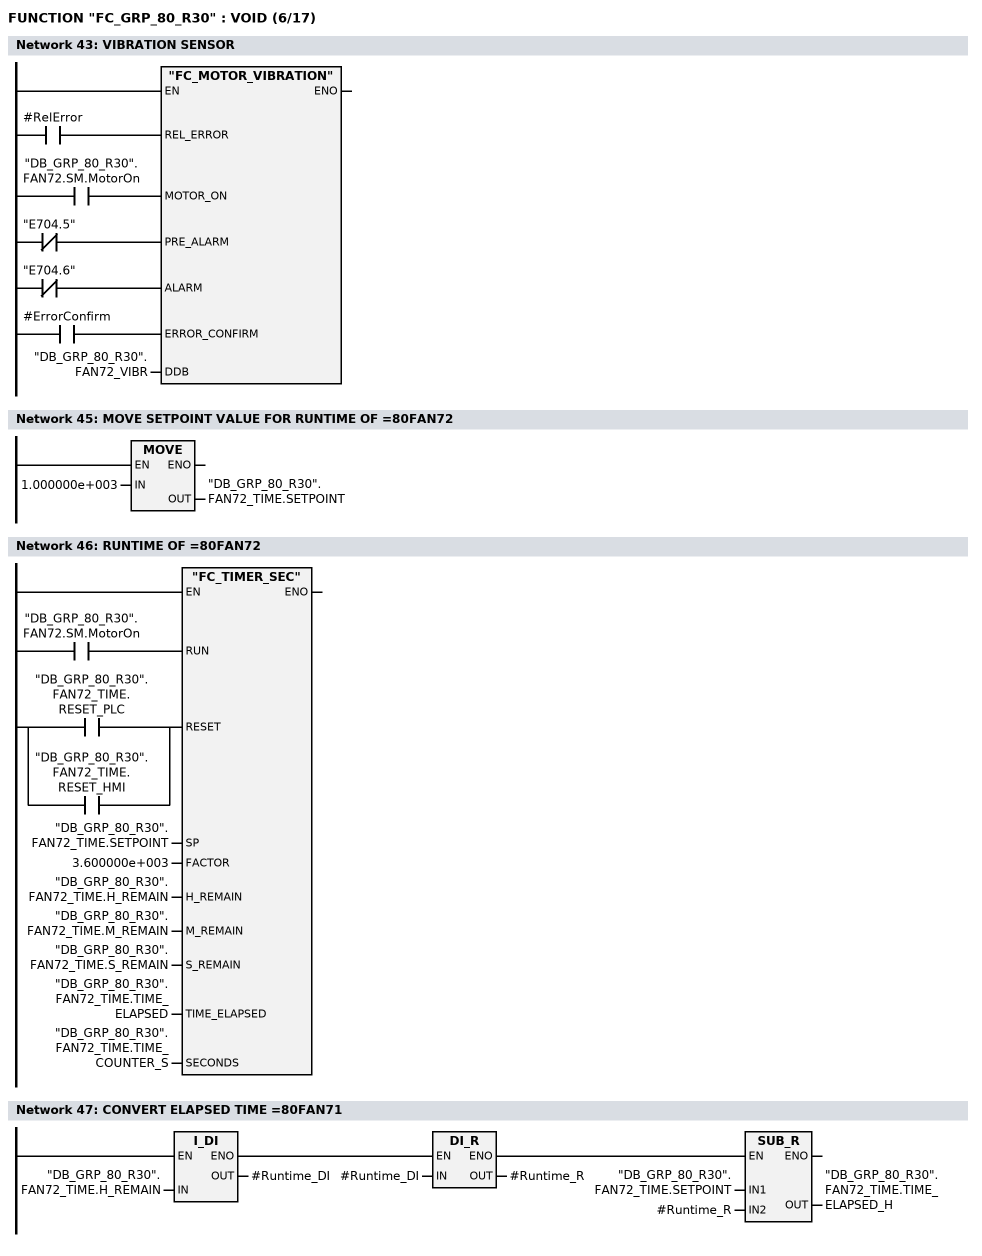
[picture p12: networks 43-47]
      U     #RelError;
      =     L     17.0;
      BLD   103;
      U     "DB_GRP_80_R30".FAN72.SM.MotorOn;
      =     L     17.1;
      BLD   103;
      UN    "E704.5";
      =     L     17.2;
      BLD   103;
      UN    "E704.6";
      =     L     17.3;
      BLD   103;
      U     #ErrorConfirm;
      =     L     17.4;
      BLD   103;
      CALL "FC_MOTOR_VIBRATION" (
           REL_ERROR                := L     17.0,
           MOTOR_ON                 := L     17.1,
           PRE_ALARM                := L     17.2,
           ALARM                    := L     17.3,
           ERROR_CONFIRM            := L     17.4,
           DDB                      := "DB_GRP_80_R30".FAN72_VIBR);
      NOP   0;
NETWORK
TITLE =****** RUNTIME METER ********



NETWORK
TITLE =MOVE SETPOINT VALUE FOR RUNTIME OF =80FAN72

      L     1.000000e+003;
      T     "DB_GRP_80_R30".FAN72_TIME.SETPOINT;
      NOP   0;
NETWORK
TITLE =RUNTIME OF =80FAN72

      U     "DB_GRP_80_R30".FAN72.SM.MotorOn;
      =     L     17.0;
      BLD   103;
      U(    ;
      O     "DB_GRP_80_R30".FAN72_TIME.RESET_PLC;
      O     "DB_GRP_80_R30".FAN72_TIME.RESET_HMI;
      )     ;
      =     L     17.1;
      BLD   103;
      CALL "FC_TIMER_SEC" (
           RUN                      := L     17.0,
           RESET                    := L     17.1,
           SP                       := "DB_GRP_80_R30".FAN72_TIME.SETPOINT,
           FACTOR                   := 3.600000e+003,
           H_REMAIN                 := "DB_GRP_80_R30".FAN72_TIME.H_REMAIN,
           M_REMAIN                 := "DB_GRP_80_R30".FAN72_TIME.M_REMAIN,
           S_REMAIN                 := "DB_GRP_80_R30".FAN72_TIME.S_REMAIN,
           TIME_ELAPSED             := "DB_GRP_80_R30".FAN72_TIME.TIME_ELAPSED,
           SECONDS                  := "DB_GRP_80_R30".FAN72_TIME.TIME_COUNTER_S);
      NOP   0;
NETWORK
TITLE =CONVERT ELAPSED TIME =80FAN71

      U(    ;
      U(    ;
      L     "DB_GRP_80_R30".FAN72_TIME.H_REMAIN;
      ITD   ;
      T     #Runtime_DI;
      SET   ;
      SAVE  ;
      CLR   ;
      U     BIE;
      )     ;
      SPBNB _007;
      L     #Runtime_DI;
      DTR   ;
      T     #Runtime_R;
      SET   ;
      SAVE  ;
      CLR   ;
_007: U     BIE;
      )     ;
      SPBNB _008;
      L     "DB_GRP_80_R30".FAN72_TIME.SETPOINT;
      L     #Runtime_R;
      -R    ;
      T     "DB_GRP_80_R30".FAN72_TIME.TIME_ELAPSED_H;
_008: NOP   0;
NETWORK
TITLE =



NETWORK
TITLE =CONTROL/ERROR RELEASE =80FAN73

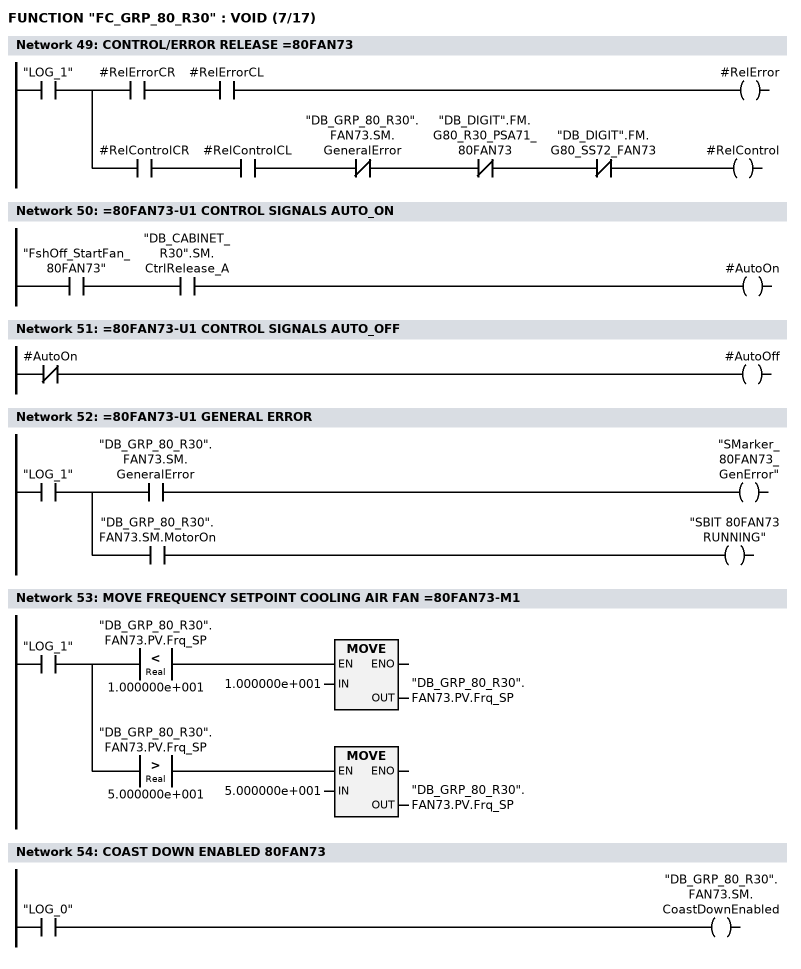
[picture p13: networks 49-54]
      U     "LOG_1";
      =     L     17.0;
      U     L     17.0;
      U     #RelErrorCR;
      U     #RelErrorCL;
      =     #RelError;
      U     L     17.0;
      U     #RelControlCR;
      U     #RelControlCL;
      UN    "DB_GRP_80_R30".FAN73.SM.GeneralError;
      UN    "DB_DIGIT".FM.G80_R30_PSA71_80FAN73;
      UN    "DB_DIGIT".FM.G80_SS72_FAN73;
      =     #RelControl;
NETWORK
TITLE ==80FAN73-U1 CONTROL SIGNALS AUTO_ON

      U     "FshOff_StartFan_80FAN73";
      U     "DB_CABINET_R30".SM.CtrlRelease_A;
      =     #AutoOn;
NETWORK
TITLE ==80FAN73-U1 CONTROL SIGNALS AUTO_OFF

      UN    #AutoOn;
      =     #AutoOff;
NETWORK
TITLE ==80FAN73-U1 GENERAL ERROR

      U     "LOG_1";
      =     L     17.0;
      U     L     17.0;
      U     "DB_GRP_80_R30".FAN73.SM.GeneralError;
      =     "SMarker_80FAN73_GenError";
      U     L     17.0;
      U     "DB_GRP_80_R30".FAN73.SM.MotorOn;
      =     "SBIT 80FAN73 RUNNING";
NETWORK
TITLE =MOVE FREQUENCY SETPOINT COOLING AIR FAN =80FAN73-M1

      U     "LOG_1";
      =     L     17.0;
      U     L     17.0;
      U(    ;
      L     "DB_GRP_80_R30".FAN73.PV.Frq_SP;
      L     1.000000e+001;
      <R    ;
      )     ;
      SPBNB _009;
      L     1.000000e+001;
      T     "DB_GRP_80_R30".FAN73.PV.Frq_SP;
_009: NOP   0;
      U     L     17.0;
      U(    ;
      L     "DB_GRP_80_R30".FAN73.PV.Frq_SP;
      L     5.000000e+001;
      >R    ;
      )     ;
      SPBNB _00a;
      L     5.000000e+001;
      T     "DB_GRP_80_R30".FAN73.PV.Frq_SP;
_00a: NOP   0;
NETWORK
TITLE =COAST DOWN ENABLED 80FAN73

      U     "LOG_0";
      =     "DB_GRP_80_R30".FAN73.SM.CoastDownEnabled;
NETWORK
TITLE ==80FAN73-U1 HEATING GROUP AIR FAN 3

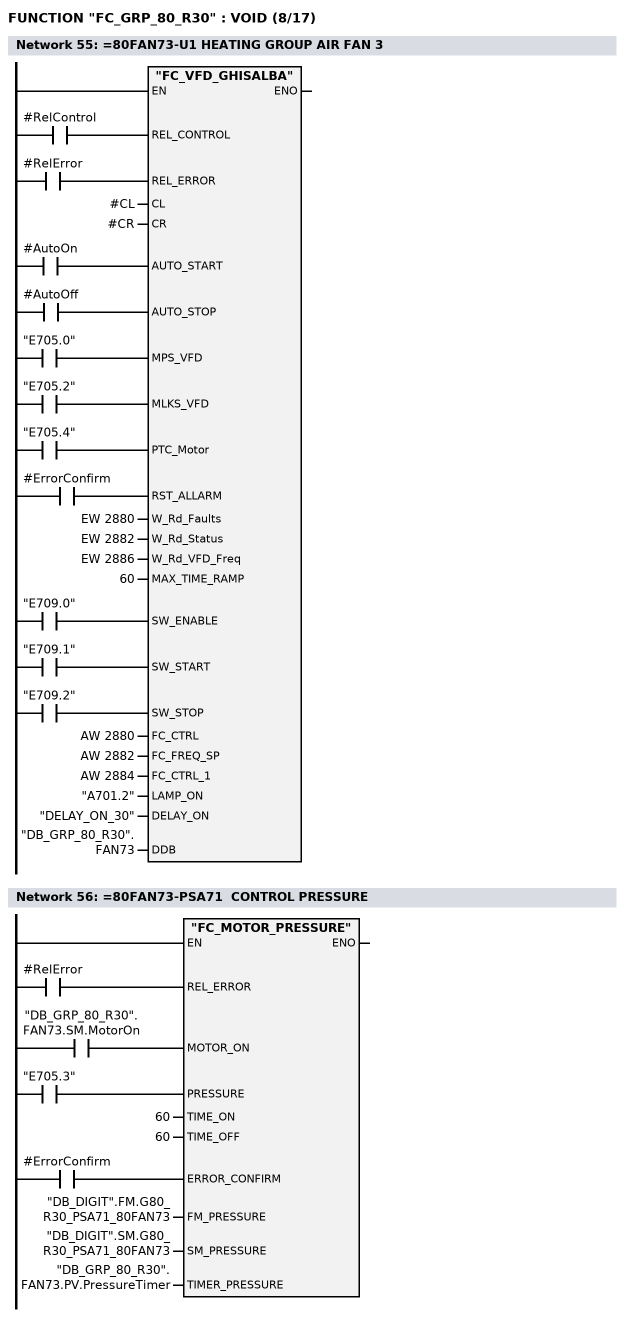
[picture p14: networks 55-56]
      U     #RelControl;
      =     L     17.0;
      BLD   103;
      U     #RelError;
      =     L     17.1;
      BLD   103;
      U     #AutoOn;
      =     L     17.2;
      BLD   103;
      U     #AutoOff;
      =     L     17.3;
      BLD   103;
      U     "E705.0";
      =     L     17.4;
      BLD   103;
      U     "E705.2";
      =     L     17.5;
      BLD   103;
      U     "E705.4";
      =     L     17.6;
      BLD   103;
      U     #ErrorConfirm;
      =     L     17.7;
      BLD   103;
      U     "E709.0";
      =     L     18.0;
      BLD   103;
      U     "E709.1";
      =     L     18.1;
      BLD   103;
      U     "E709.2";
      =     L     18.2;
      BLD   103;
      CALL "FC_VFD_GHISALBA" (
           REL_CONTROL              := L     17.0,
           REL_ERROR                := L     17.1,
           CL                       := #CL,
           CR                       := #CR,
           AUTO_START               := L     17.2,
           AUTO_STOP                := L     17.3,
           MPS_VFD                  := L     17.4,
           MLKS_VFD                 := L     17.5,
           PTC_Motor                := L     17.6,
           RST_ALLARM               := L     17.7,
           W_Rd_Faults              := EW  2880,
           W_Rd_Status              := EW  2882,
           W_Rd_VFD_Freq            := EW  2886,
           MAX_TIME_RAMP            := 60,
           SW_ENABLE                := L     18.0,
           SW_START                 := L     18.1,
           SW_STOP                  := L     18.2,
           FC_CTRL                  := AW  2880,
           FC_FREQ_SP               := AW  2882,
           FC_CTRL_1                := AW  2884,
           LAMP_ON                  := "A701.2",
           DELAY_ON                 := "DELAY_ON_30",
           DDB                      := "DB_GRP_80_R30".FAN73);
      NOP   0;
NETWORK
TITLE ==80FAN73-PSA71  CONTROL PRESSURE

      U     #RelError;
      =     L     17.0;
      BLD   103;
      U     "DB_GRP_80_R30".FAN73.SM.MotorOn;
      =     L     17.1;
      BLD   103;
      U     "E705.3";
      =     L     17.2;
      BLD   103;
      U     #ErrorConfirm;
      =     L     17.3;
      BLD   103;
      CALL "FC_MOTOR_PRESSURE" (
           REL_ERROR                := L     17.0,
           MOTOR_ON                 := L     17.1,
           PRESSURE                 := L     17.2,
           TIME_ON                  := 60,
           TIME_OFF                 := 60,
           ERROR_CONFIRM            := L     17.3,
           FM_PRESSURE              := "DB_DIGIT".FM.G80_R30_PSA71_80FAN73,
           SM_PRESSURE              := "DB_DIGIT".SM.G80_R30_PSA71_80FAN73,
           TIMER_PRESSURE           := "DB_GRP_80_R30".FAN73.PV.PressureTimer);
      NOP   0;
NETWORK
TITLE =VIBRATION SENSOR

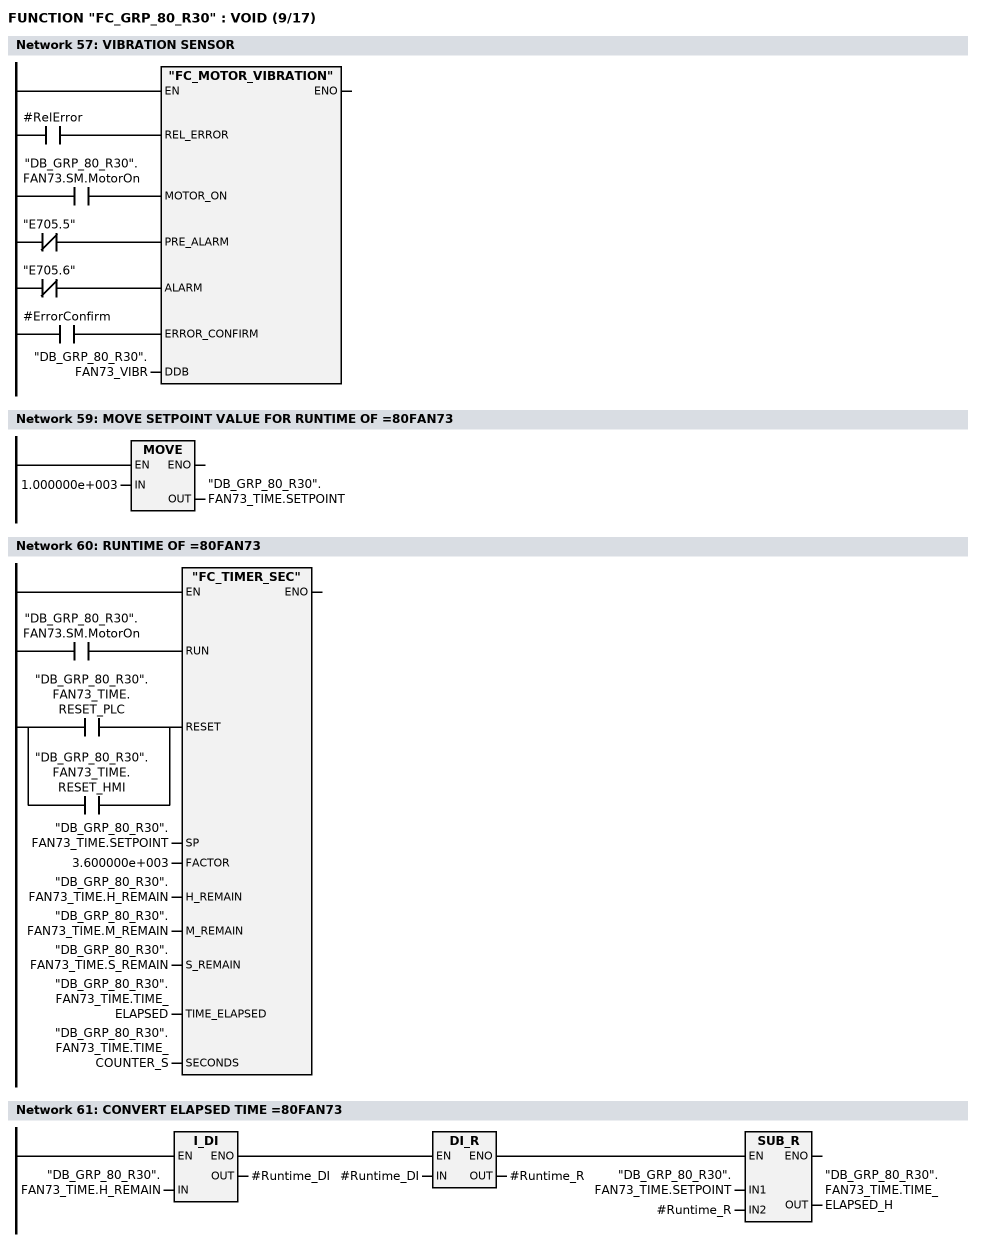
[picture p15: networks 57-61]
      U     #RelError;
      =     L     17.0;
      BLD   103;
      U     "DB_GRP_80_R30".FAN73.SM.MotorOn;
      =     L     17.1;
      BLD   103;
      UN    "E705.5";
      =     L     17.2;
      BLD   103;
      UN    "E705.6";
      =     L     17.3;
      BLD   103;
      U     #ErrorConfirm;
      =     L     17.4;
      BLD   103;
      CALL "FC_MOTOR_VIBRATION" (
           REL_ERROR                := L     17.0,
           MOTOR_ON                 := L     17.1,
           PRE_ALARM                := L     17.2,
           ALARM                    := L     17.3,
           ERROR_CONFIRM            := L     17.4,
           DDB                      := "DB_GRP_80_R30".FAN73_VIBR);
      NOP   0;
NETWORK
TITLE =****** RUNTIME METER ********



NETWORK
TITLE =MOVE SETPOINT VALUE FOR RUNTIME OF =80FAN73

      L     1.000000e+003;
      T     "DB_GRP_80_R30".FAN73_TIME.SETPOINT;
      NOP   0;
NETWORK
TITLE =RUNTIME OF =80FAN73

      U     "DB_GRP_80_R30".FAN73.SM.MotorOn;
      =     L     17.0;
      BLD   103;
      U(    ;
      O     "DB_GRP_80_R30".FAN73_TIME.RESET_PLC;
      O     "DB_GRP_80_R30".FAN73_TIME.RESET_HMI;
      )     ;
      =     L     17.1;
      BLD   103;
      CALL "FC_TIMER_SEC" (
           RUN                      := L     17.0,
           RESET                    := L     17.1,
           SP                       := "DB_GRP_80_R30".FAN73_TIME.SETPOINT,
           FACTOR                   := 3.600000e+003,
           H_REMAIN                 := "DB_GRP_80_R30".FAN73_TIME.H_REMAIN,
           M_REMAIN                 := "DB_GRP_80_R30".FAN73_TIME.M_REMAIN,
           S_REMAIN                 := "DB_GRP_80_R30".FAN73_TIME.S_REMAIN,
           TIME_ELAPSED             := "DB_GRP_80_R30".FAN73_TIME.TIME_ELAPSED,
           SECONDS                  := "DB_GRP_80_R30".FAN73_TIME.TIME_COUNTER_S);
      NOP   0;
NETWORK
TITLE =CONVERT ELAPSED TIME =80FAN73

      U(    ;
      U(    ;
      L     "DB_GRP_80_R30".FAN73_TIME.H_REMAIN;
      ITD   ;
      T     #Runtime_DI;
      SET   ;
      SAVE  ;
      CLR   ;
      U     BIE;
      )     ;
      SPBNB _00b;
      L     #Runtime_DI;
      DTR   ;
      T     #Runtime_R;
      SET   ;
      SAVE  ;
      CLR   ;
_00b: U     BIE;
      )     ;
      SPBNB _00c;
      L     "DB_GRP_80_R30".FAN73_TIME.SETPOINT;
      L     #Runtime_R;
      -R    ;
      T     "DB_GRP_80_R30".FAN73_TIME.TIME_ELAPSED_H;
_00c: NOP   0;
NETWORK
TITLE =



NETWORK
TITLE =CONTROL/ERROR RELEASE =80FAN74

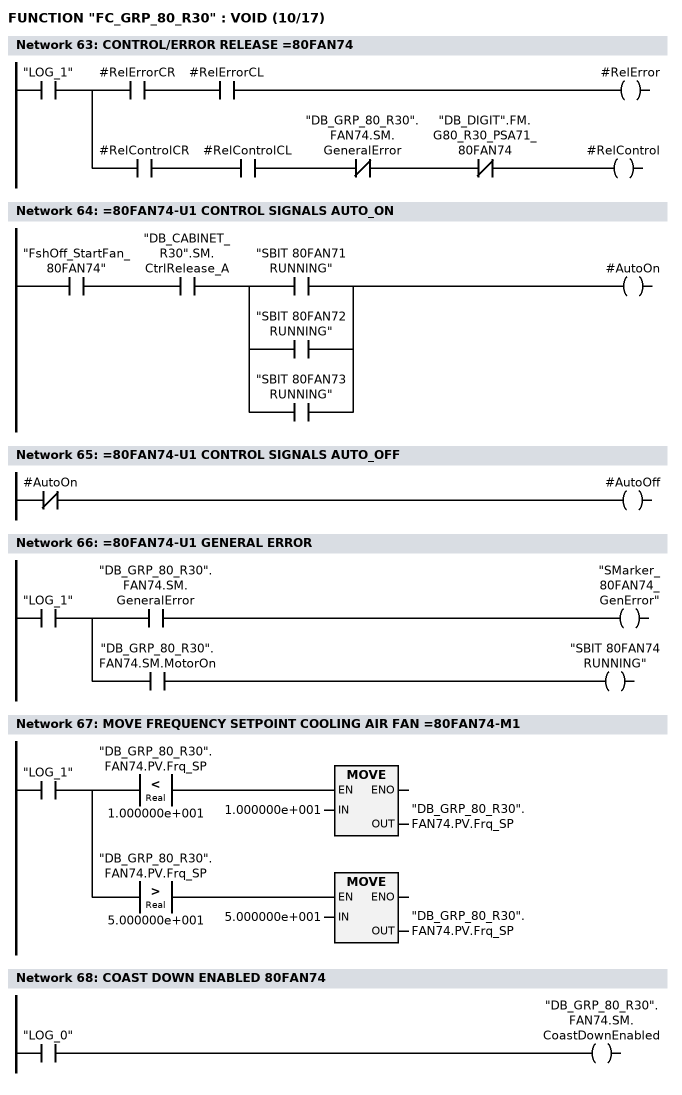
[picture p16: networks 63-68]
      U     "LOG_1";
      =     L     17.0;
      U     L     17.0;
      U     #RelErrorCR;
      U     #RelErrorCL;
      =     #RelError;
      U     L     17.0;
      U     #RelControlCR;
      U     #RelControlCL;
      UN    "DB_GRP_80_R30".FAN74.SM.GeneralError;
      UN    "DB_DIGIT".FM.G80_R30_PSA71_80FAN74;
      =     #RelControl;
NETWORK
TITLE ==80FAN74-U1 CONTROL SIGNALS AUTO_ON

      U     "FshOff_StartFan_80FAN74";
      U     "DB_CABINET_R30".SM.CtrlRelease_A;
      U(    ;
      O     "SBIT 80FAN71 RUNNING";
      O     "SBIT 80FAN72 RUNNING";
      O     "SBIT 80FAN73 RUNNING";
      )     ;
      =     #AutoOn;
NETWORK
TITLE ==80FAN74-U1 CONTROL SIGNALS AUTO_OFF

      UN    #AutoOn;
      =     #AutoOff;
NETWORK
TITLE ==80FAN74-U1 GENERAL ERROR

      U     "LOG_1";
      =     L     17.0;
      U     L     17.0;
      U     "DB_GRP_80_R30".FAN74.SM.GeneralError;
      =     "SMarker_80FAN74_GenError";
      U     L     17.0;
      U     "DB_GRP_80_R30".FAN74.SM.MotorOn;
      =     "SBIT 80FAN74 RUNNING";
NETWORK
TITLE =MOVE FREQUENCY SETPOINT COOLING AIR FAN =80FAN74-M1

      U     "LOG_1";
      =     L     17.0;
      U     L     17.0;
      U(    ;
      L     "DB_GRP_80_R30".FAN74.PV.Frq_SP;
      L     1.000000e+001;
      <R    ;
      )     ;
      SPBNB _00d;
      L     1.000000e+001;
      T     "DB_GRP_80_R30".FAN74.PV.Frq_SP;
_00d: NOP   0;
      U     L     17.0;
      U(    ;
      L     "DB_GRP_80_R30".FAN74.PV.Frq_SP;
      L     5.000000e+001;
      >R    ;
      )     ;
      SPBNB _00e;
      L     5.000000e+001;
      T     "DB_GRP_80_R30".FAN74.PV.Frq_SP;
_00e: NOP   0;
NETWORK
TITLE =COAST DOWN ENABLED 80FAN74

      U     "LOG_0";
      =     "DB_GRP_80_R30".FAN74.SM.CoastDownEnabled;
NETWORK
TITLE ==80FAN74-U1 EXHAUST FAN

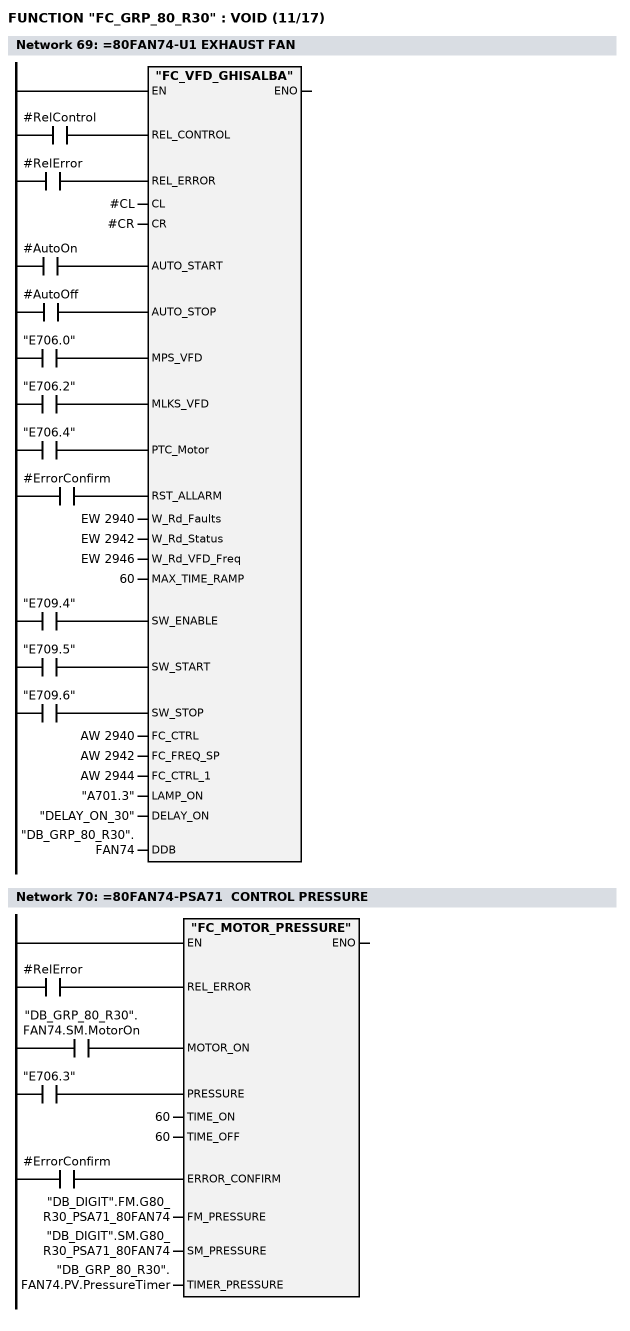
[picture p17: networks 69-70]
      U     #RelControl;
      =     L     17.0;
      BLD   103;
      U     #RelError;
      =     L     17.1;
      BLD   103;
      U     #AutoOn;
      =     L     17.2;
      BLD   103;
      U     #AutoOff;
      =     L     17.3;
      BLD   103;
      U     "E706.0";
      =     L     17.4;
      BLD   103;
      U     "E706.2";
      =     L     17.5;
      BLD   103;
      U     "E706.4";
      =     L     17.6;
      BLD   103;
      U     #ErrorConfirm;
      =     L     17.7;
      BLD   103;
      U     "E709.4";
      =     L     18.0;
      BLD   103;
      U     "E709.5";
      =     L     18.1;
      BLD   103;
      U     "E709.6";
      =     L     18.2;
      BLD   103;
      CALL "FC_VFD_GHISALBA" (
           REL_CONTROL              := L     17.0,
           REL_ERROR                := L     17.1,
           CL                       := #CL,
           CR                       := #CR,
           AUTO_START               := L     17.2,
           AUTO_STOP                := L     17.3,
           MPS_VFD                  := L     17.4,
           MLKS_VFD                 := L     17.5,
           PTC_Motor                := L     17.6,
           RST_ALLARM               := L     17.7,
           W_Rd_Faults              := EW  2940,
           W_Rd_Status              := EW  2942,
           W_Rd_VFD_Freq            := EW  2946,
           MAX_TIME_RAMP            := 60,
           SW_ENABLE                := L     18.0,
           SW_START                 := L     18.1,
           SW_STOP                  := L     18.2,
           FC_CTRL                  := AW  2940,
           FC_FREQ_SP               := AW  2942,
           FC_CTRL_1                := AW  2944,
           LAMP_ON                  := "A701.3",
           DELAY_ON                 := "DELAY_ON_30",
           DDB                      := "DB_GRP_80_R30".FAN74);
      NOP   0;
NETWORK
TITLE ==80FAN74-PSA71  CONTROL PRESSURE

      U     #RelError;
      =     L     17.0;
      BLD   103;
      U     "DB_GRP_80_R30".FAN74.SM.MotorOn;
      =     L     17.1;
      BLD   103;
      U     "E706.3";
      =     L     17.2;
      BLD   103;
      U     #ErrorConfirm;
      =     L     17.3;
      BLD   103;
      CALL "FC_MOTOR_PRESSURE" (
           REL_ERROR                := L     17.0,
           MOTOR_ON                 := L     17.1,
           PRESSURE                 := L     17.2,
           TIME_ON                  := 60,
           TIME_OFF                 := 60,
           ERROR_CONFIRM            := L     17.3,
           FM_PRESSURE              := "DB_DIGIT".FM.G80_R30_PSA71_80FAN74,
           SM_PRESSURE              := "DB_DIGIT".SM.G80_R30_PSA71_80FAN74,
           TIMER_PRESSURE           := "DB_GRP_80_R30".FAN74.PV.PressureTimer);
      NOP   0;
NETWORK
TITLE =VIBRATION SENSOR

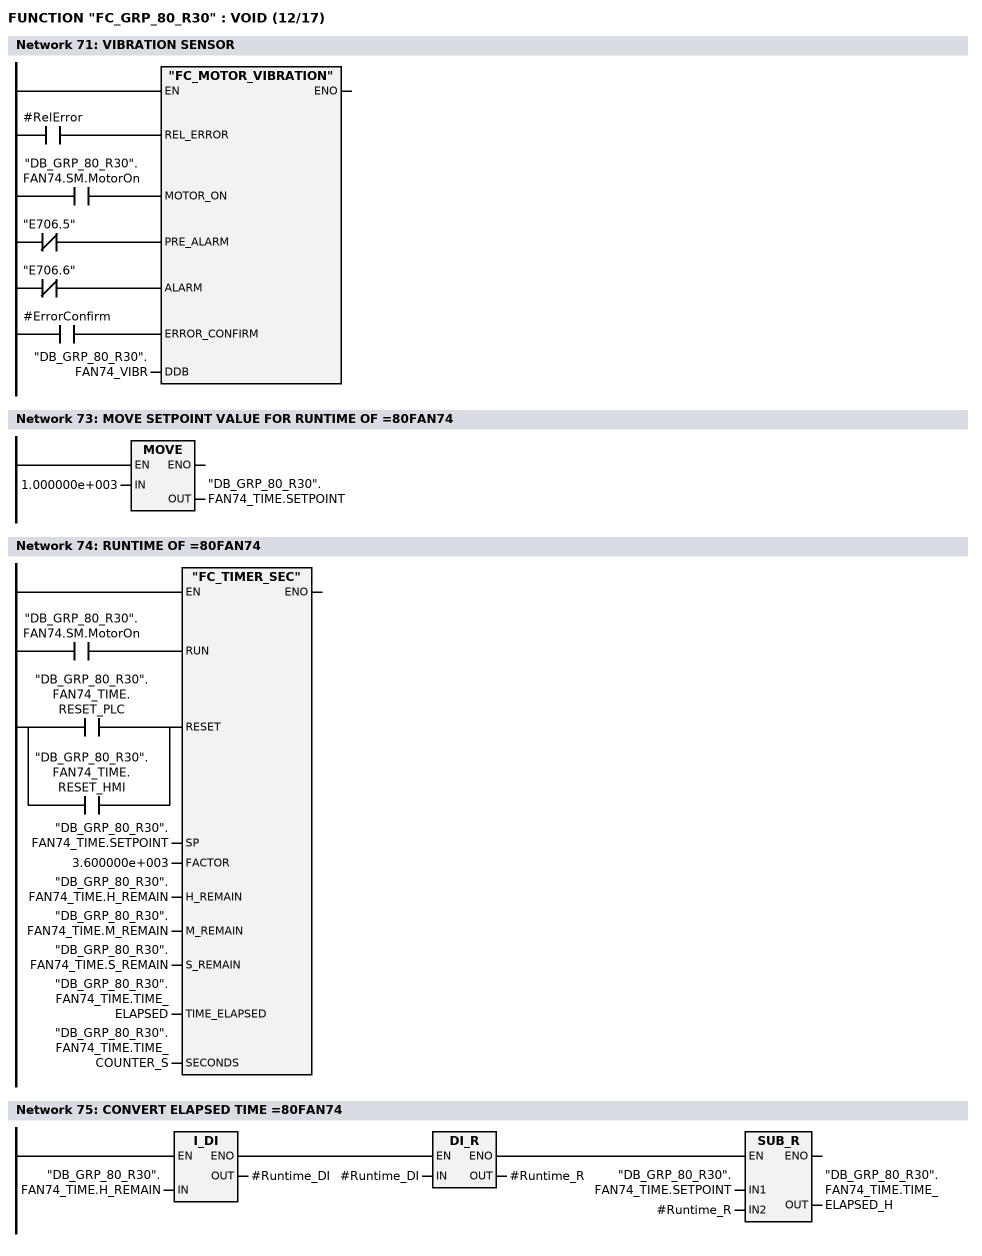
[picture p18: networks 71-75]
      U     #RelError;
      =     L     17.0;
      BLD   103;
      U     "DB_GRP_80_R30".FAN74.SM.MotorOn;
      =     L     17.1;
      BLD   103;
      UN    "E706.5";
      =     L     17.2;
      BLD   103;
      UN    "E706.6";
      =     L     17.3;
      BLD   103;
      U     #ErrorConfirm;
      =     L     17.4;
      BLD   103;
      CALL "FC_MOTOR_VIBRATION" (
           REL_ERROR                := L     17.0,
           MOTOR_ON                 := L     17.1,
           PRE_ALARM                := L     17.2,
           ALARM                    := L     17.3,
           ERROR_CONFIRM            := L     17.4,
           DDB                      := "DB_GRP_80_R30".FAN74_VIBR);
      NOP   0;
NETWORK
TITLE =****** RUNTIME METER ********



NETWORK
TITLE =MOVE SETPOINT VALUE FOR RUNTIME OF =80FAN74

      L     1.000000e+003;
      T     "DB_GRP_80_R30".FAN74_TIME.SETPOINT;
      NOP   0;
NETWORK
TITLE =RUNTIME OF =80FAN74

      U     "DB_GRP_80_R30".FAN74.SM.MotorOn;
      =     L     17.0;
      BLD   103;
      U(    ;
      O     "DB_GRP_80_R30".FAN74_TIME.RESET_PLC;
      O     "DB_GRP_80_R30".FAN74_TIME.RESET_HMI;
      )     ;
      =     L     17.1;
      BLD   103;
      CALL "FC_TIMER_SEC" (
           RUN                      := L     17.0,
           RESET                    := L     17.1,
           SP                       := "DB_GRP_80_R30".FAN74_TIME.SETPOINT,
           FACTOR                   := 3.600000e+003,
           H_REMAIN                 := "DB_GRP_80_R30".FAN74_TIME.H_REMAIN,
           M_REMAIN                 := "DB_GRP_80_R30".FAN74_TIME.M_REMAIN,
           S_REMAIN                 := "DB_GRP_80_R30".FAN74_TIME.S_REMAIN,
           TIME_ELAPSED             := "DB_GRP_80_R30".FAN74_TIME.TIME_ELAPSED,
           SECONDS                  := "DB_GRP_80_R30".FAN74_TIME.TIME_COUNTER_S);
      NOP   0;
NETWORK
TITLE =CONVERT ELAPSED TIME =80FAN74

      U(    ;
      U(    ;
      L     "DB_GRP_80_R30".FAN74_TIME.H_REMAIN;
      ITD   ;
      T     #Runtime_DI;
      SET   ;
      SAVE  ;
      CLR   ;
      U     BIE;
      )     ;
      SPBNB _00f;
      L     #Runtime_DI;
      DTR   ;
      T     #Runtime_R;
      SET   ;
      SAVE  ;
      CLR   ;
_00f: U     BIE;
      )     ;
      SPBNB _010;
      L     "DB_GRP_80_R30".FAN74_TIME.SETPOINT;
      L     #Runtime_R;
      -R    ;
      T     "DB_GRP_80_R30".FAN74_TIME.TIME_ELAPSED_H;
_010: NOP   0;
NETWORK
TITLE =



NETWORK
TITLE ==TSA71 80FAN71 MOTOR THERMAL PROBE OK

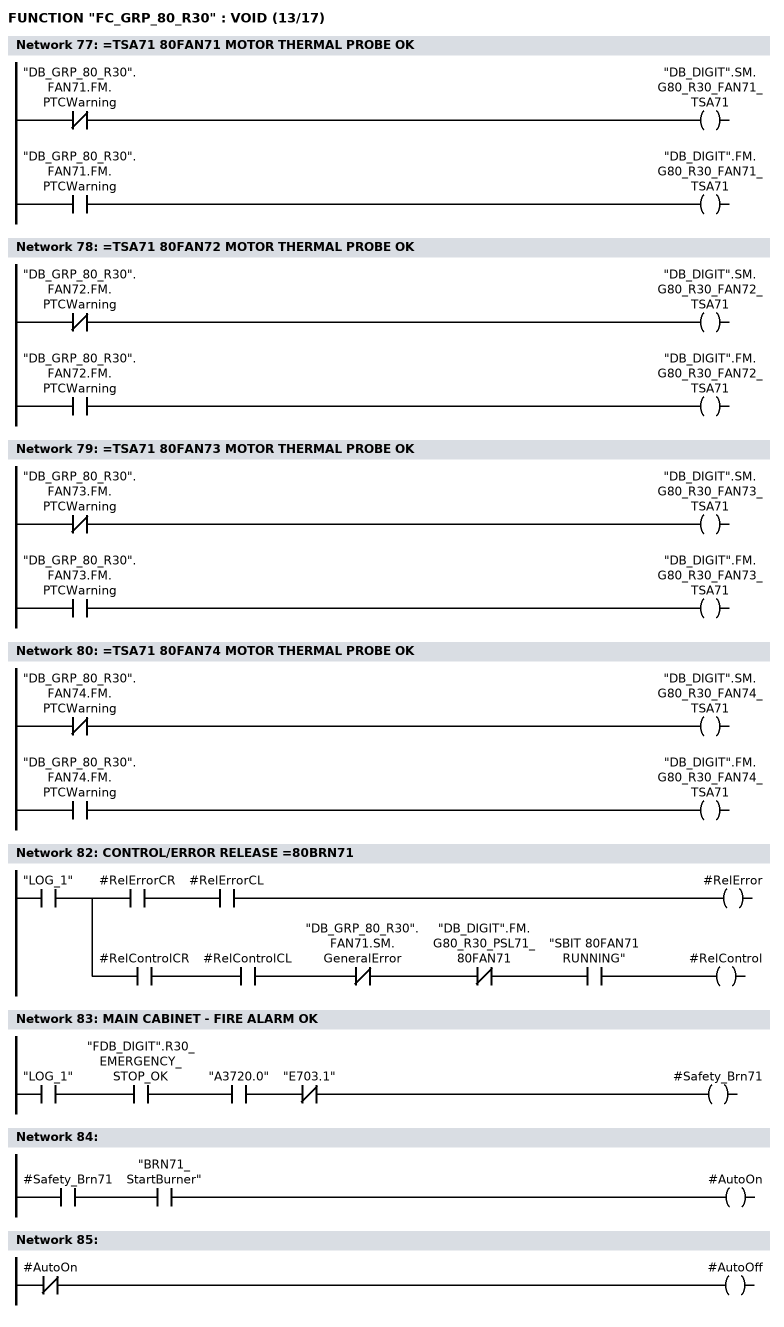
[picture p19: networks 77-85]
      UN    "DB_GRP_80_R30".FAN71.FM.PTCWarning;
      =     "DB_DIGIT".SM.G80_R30_FAN71_TSA71;
      U     "DB_GRP_80_R30".FAN71.FM.PTCWarning;
      =     "DB_DIGIT".FM.G80_R30_FAN71_TSA71;

NETWORK
TITLE ==TSA71 80FAN72 MOTOR THERMAL PROBE OK

      UN    "DB_GRP_80_R30".FAN72.FM.PTCWarning;
      =     "DB_DIGIT".SM.G80_R30_FAN72_TSA71;
      U     "DB_GRP_80_R30".FAN72.FM.PTCWarning;
      =     "DB_DIGIT".FM.G80_R30_FAN72_TSA71;

NETWORK
TITLE ==TSA71 80FAN73 MOTOR THERMAL PROBE OK

      UN    "DB_GRP_80_R30".FAN73.FM.PTCWarning;
      =     "DB_DIGIT".SM.G80_R30_FAN73_TSA71;
      U     "DB_GRP_80_R30".FAN73.FM.PTCWarning;
      =     "DB_DIGIT".FM.G80_R30_FAN73_TSA71;

NETWORK
TITLE ==TSA71 80FAN74 MOTOR THERMAL PROBE OK

      UN    "DB_GRP_80_R30".FAN74.FM.PTCWarning;
      =     "DB_DIGIT".SM.G80_R30_FAN74_TSA71;
      U     "DB_GRP_80_R30".FAN74.FM.PTCWarning;
      =     "DB_DIGIT".FM.G80_R30_FAN74_TSA71;

NETWORK
TITLE =



NETWORK
TITLE =CONTROL/ERROR RELEASE =80BRN71

      U     "LOG_1";
      =     L     17.0;
      U     L     17.0;
      U     #RelErrorCR;
      U     #RelErrorCL;
      =     #RelError;
      U     L     17.0;
      U     #RelControlCR;
      U     #RelControlCL;
      UN    "DB_GRP_80_R30".FAN71.SM.GeneralError;
      UN    "DB_DIGIT".FM.G80_R30_PSL71_80FAN71;
      U     "SBIT 80FAN71 RUNNING";
      =     #RelControl;
NETWORK
TITLE =MAIN CABINET - FIRE ALARM OK

      U     "LOG_1";
      U     "FDB_DIGIT".R30_EMERGENCY_STOP_OK;
      U     "A3720.0";
      UN    "E703.1";
      =     #Safety_Brn71;
NETWORK
TITLE =

      U     #Safety_Brn71;
      U     "BRN71_StartBurner";
      =     #AutoOn;
NETWORK
TITLE =

      UN    #AutoOn;
      =     #AutoOff;
NETWORK
TITLE =

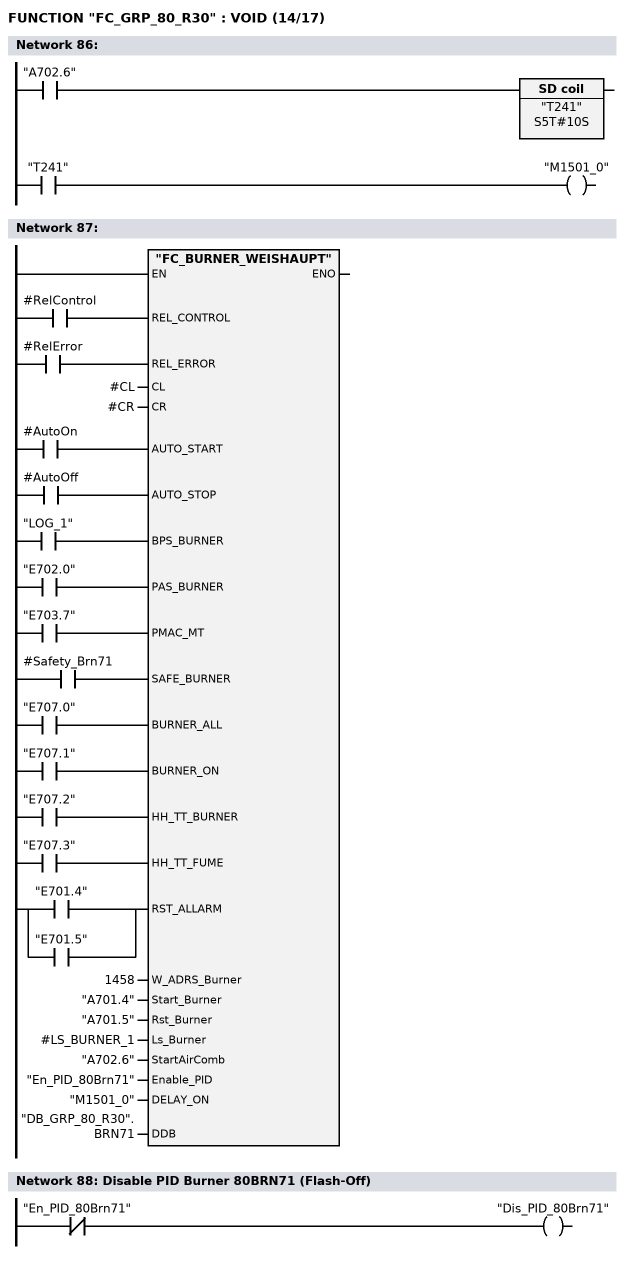
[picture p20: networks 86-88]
      U     "A702.6";
      L     S5T#10S;
      SE    "T241";
      NOP   0;
      NOP   0;
      NOP   0;
      U     "T241";
      =     "M1501_0";
NETWORK
TITLE =

      U     #RelControl;
      =     L     17.0;
      BLD   103;
      U     #RelError;
      =     L     17.1;
      BLD   103;
      U     #AutoOn;
      =     L     17.2;
      BLD   103;
      U     #AutoOff;
      =     L     17.3;
      BLD   103;
      U     "LOG_1";
      =     L     17.4;
      BLD   103;
      U     "E702.0";
      =     L     17.5;
      BLD   103;
      U     "E703.7";
      =     L     17.6;
      BLD   103;
      U     #Safety_Brn71;
      =     L     17.7;
      BLD   103;
      U     "E707.0";
      =     L     18.0;
      BLD   103;
      U     "E707.1";
      =     L     18.1;
      BLD   103;
      U     "E707.2";
      =     L     18.2;
      BLD   103;
      U     "E707.3";
      =     L     18.3;
      BLD   103;
      U(    ;
      O     "E701.4";
      O     "E701.5";
      )     ;
      =     L     18.4;
      BLD   103;
      CALL "FC_BURNER_WEISHAUPT" (
           REL_CONTROL              := L     17.0,
           REL_ERROR                := L     17.1,
           CL                       := #CL,
           CR                       := #CR,
           AUTO_START               := L     17.2,
           AUTO_STOP                := L     17.3,
           BPS_BURNER               := L     17.4,
           PAS_BURNER               := L     17.5,
           PMAC_MT                  := L     17.6,
           SAFE_BURNER              := L     17.7,
           BURNER_ALL               := L     18.0,
           BURNER_ON                := L     18.1,
           HH_TT_BURNER             := L     18.2,
           HH_TT_FUME               := L     18.3,
           RST_ALLARM               := L     18.4,
           W_ADRS_Burner            := 1458,
           Start_Burner             := "A701.4",
           Rst_Burner               := "A701.5",
           Ls_Burner                := #LS_BURNER_1,
           StartAirComb             := "A702.6",
           Enable_PID               := "En_PID_80Brn71",
           DELAY_ON                 := "M1501_0",
           DDB                      := "DB_GRP_80_R30".BRN71);
      NOP   0;
NETWORK
TITLE =Disable PID Burner 80BRN71 (Flash-Off)

      UN    "En_PID_80Brn71";
      =     "Dis_PID_80Brn71";
NETWORK
TITLE =



NETWORK
TITLE =CONTROL/ERROR RELEASE =80BRN72

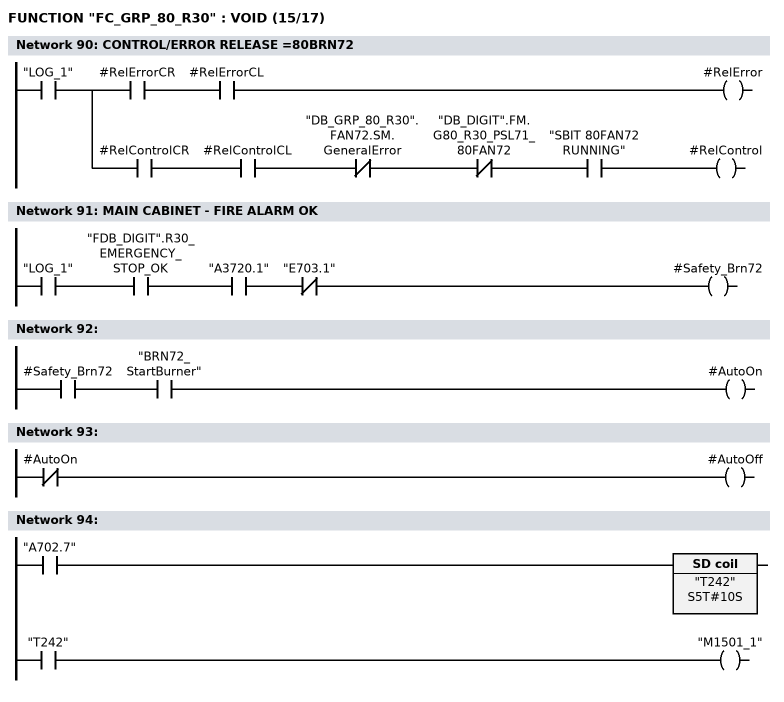
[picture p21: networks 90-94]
      U     "LOG_1";
      =     L     17.0;
      U     L     17.0;
      U     #RelErrorCR;
      U     #RelErrorCL;
      =     #RelError;
      U     L     17.0;
      U     #RelControlCR;
      U     #RelControlCL;
      UN    "DB_GRP_80_R30".FAN72.SM.GeneralError;
      UN    "DB_DIGIT".FM.G80_R30_PSL71_80FAN72;
      U     "SBIT 80FAN72 RUNNING";
      =     #RelControl;
NETWORK
TITLE =MAIN CABINET - FIRE ALARM OK

      U     "LOG_1";
      U     "FDB_DIGIT".R30_EMERGENCY_STOP_OK;
      U     "A3720.1";
      UN    "E703.1";
      =     #Safety_Brn72;
NETWORK
TITLE =

      U     #Safety_Brn72;
      U     "BRN72_StartBurner";
      =     #AutoOn;
NETWORK
TITLE =

      UN    #AutoOn;
      =     #AutoOff;
NETWORK
TITLE =

      U     "A702.7";
      L     S5T#10S;
      SE    "T242";
      NOP   0;
      NOP   0;
      NOP   0;
      U     "T242";
      =     "M1501_1";
NETWORK
TITLE =

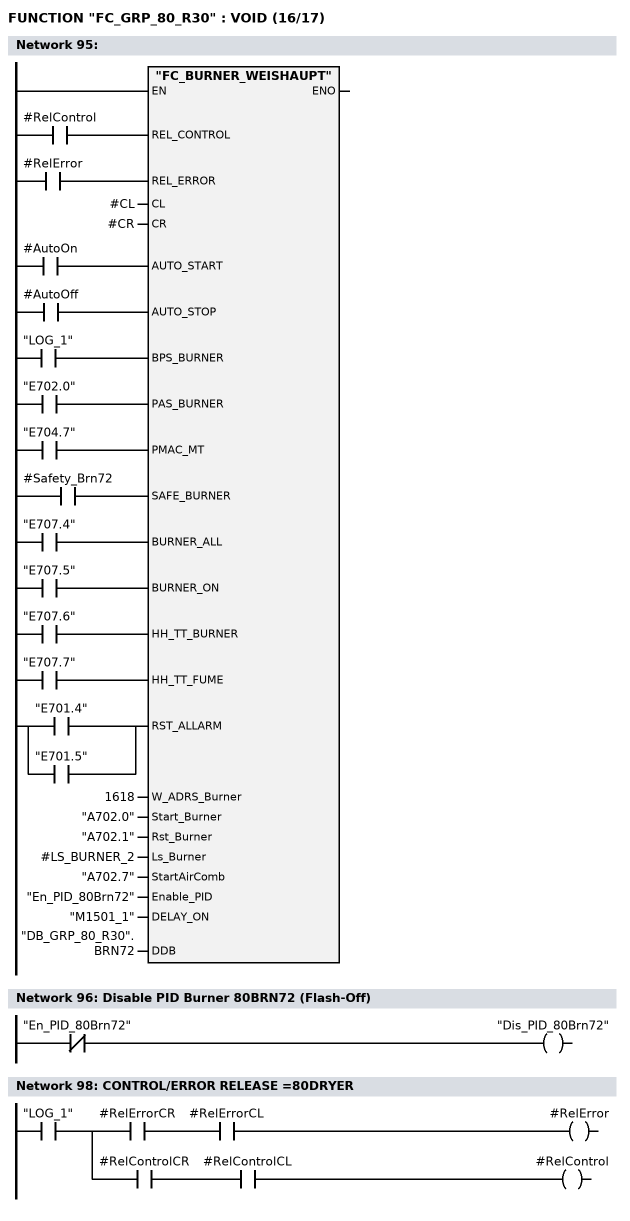
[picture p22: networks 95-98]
      U     #RelControl;
      =     L     17.0;
      BLD   103;
      U     #RelError;
      =     L     17.1;
      BLD   103;
      U     #AutoOn;
      =     L     17.2;
      BLD   103;
      U     #AutoOff;
      =     L     17.3;
      BLD   103;
      U     "LOG_1";
      =     L     17.4;
      BLD   103;
      U     "E702.0";
      =     L     17.5;
      BLD   103;
      U     "E704.7";
      =     L     17.6;
      BLD   103;
      U     #Safety_Brn72;
      =     L     17.7;
      BLD   103;
      U     "E707.4";
      =     L     18.0;
      BLD   103;
      U     "E707.5";
      =     L     18.1;
      BLD   103;
      U     "E707.6";
      =     L     18.2;
      BLD   103;
      U     "E707.7";
      =     L     18.3;
      BLD   103;
      U(    ;
      O     "E701.4";
      O     "E701.5";
      )     ;
      =     L     18.4;
      BLD   103;
      CALL "FC_BURNER_WEISHAUPT" (
           REL_CONTROL              := L     17.0,
           REL_ERROR                := L     17.1,
           CL                       := #CL,
           CR                       := #CR,
           AUTO_START               := L     17.2,
           AUTO_STOP                := L     17.3,
           BPS_BURNER               := L     17.4,
           PAS_BURNER               := L     17.5,
           PMAC_MT                  := L     17.6,
           SAFE_BURNER              := L     17.7,
           BURNER_ALL               := L     18.0,
           BURNER_ON                := L     18.1,
           HH_TT_BURNER             := L     18.2,
           HH_TT_FUME               := L     18.3,
           RST_ALLARM               := L     18.4,
           W_ADRS_Burner            := 1618,
           Start_Burner             := "A702.0",
           Rst_Burner               := "A702.1",
           Ls_Burner                := #LS_BURNER_2,
           StartAirComb             := "A702.7",
           Enable_PID               := "En_PID_80Brn72",
           DELAY_ON                 := "M1501_1",
           DDB                      := "DB_GRP_80_R30".BRN72);
      NOP   0;
NETWORK
TITLE =Disable PID Burner 80BRN72 (Flash-Off)

      UN    "En_PID_80Brn72";
      =     "Dis_PID_80Brn72";
NETWORK
TITLE =



NETWORK
TITLE =CONTROL/ERROR RELEASE =80DRYER

      U     "LOG_1";
      =     L     17.0;
      U     L     17.0;
      U     #RelErrorCR;
      U     #RelErrorCL;
      =     #RelError;
      U     L     17.0;
      U     #RelControlCR;
      U     #RelControlCL;
      =     #RelControl;
NETWORK
TITLE ==DRYER CONTROL SIGNALS AUTO_ON

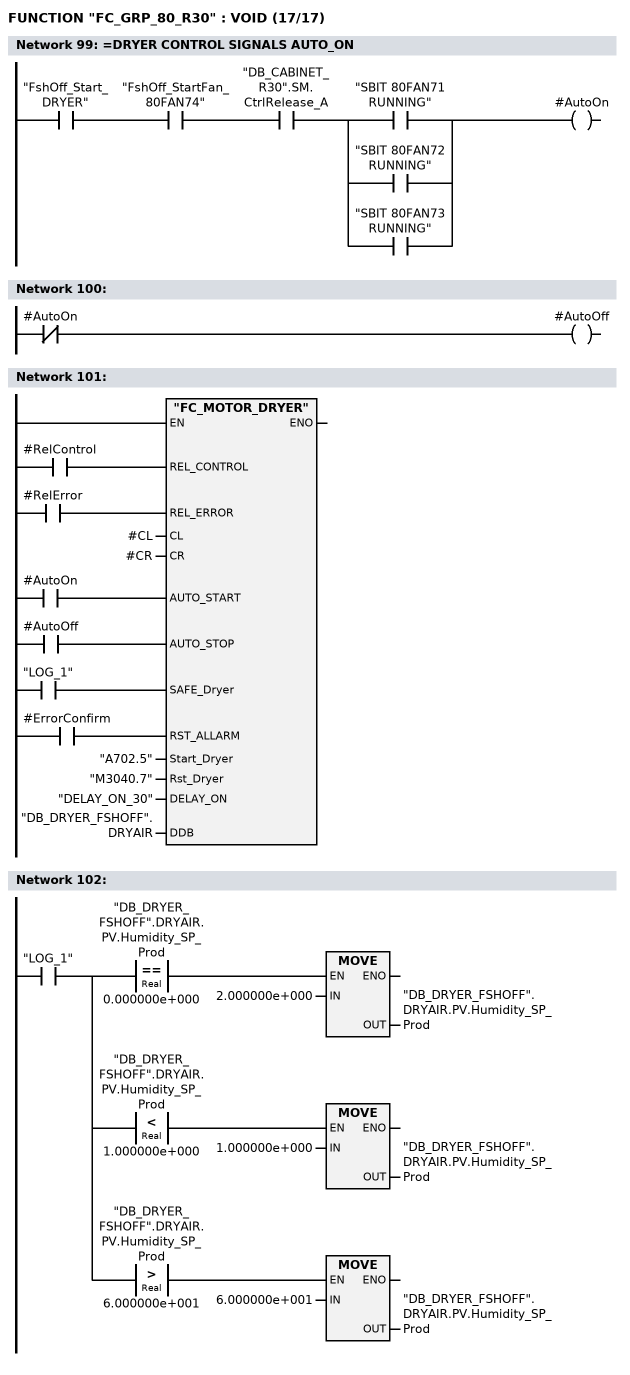
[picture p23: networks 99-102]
      U     "FshOff_Start_DRYER";
      U     "FshOff_StartFan_80FAN74";
      U     "DB_CABINET_R30".SM.CtrlRelease_A;
      U(    ;
      O     "SBIT 80FAN71 RUNNING";
      O     "SBIT 80FAN72 RUNNING";
      O     "SBIT 80FAN73 RUNNING";
      )     ;
      =     #AutoOn;
NETWORK
TITLE =

      UN    #AutoOn;
      =     #AutoOff;
NETWORK
TITLE =

      U     #RelControl;
      =     L     17.0;
      BLD   103;
      U     #RelError;
      =     L     17.1;
      BLD   103;
      U     #AutoOn;
      =     L     17.2;
      BLD   103;
      U     #AutoOff;
      =     L     17.3;
      BLD   103;
      U     "LOG_1";
      =     L     17.4;
      BLD   103;
      U     #ErrorConfirm;
      =     L     17.5;
      BLD   103;
      CALL "FC_MOTOR_DRYER" (
           REL_CONTROL              := L     17.0,
           REL_ERROR                := L     17.1,
           CL                       := #CL,
           CR                       := #CR,
           AUTO_START               := L     17.2,
           AUTO_STOP                := L     17.3,
           SAFE_Dryer               := L     17.4,
           RST_ALLARM               := L     17.5,
           Start_Dryer              := "A702.5",
           Rst_Dryer                := "M3040.7",
           DELAY_ON                 := "DELAY_ON_30",
           DDB                      := "DB_DRYER_FSHOFF".DRYAIR);
      NOP   0;
NETWORK
TITLE =

      U     "LOG_1";
      =     L     17.0;
      U     L     17.0;
      U(    ;
      L     "DB_DRYER_FSHOFF".DRYAIR.PV.Humidity_SP_Prod;
      L     0.000000e+000;
      ==R   ;
      )     ;
      SPBNB _011;
      L     2.000000e+000;
      T     "DB_DRYER_FSHOFF".DRYAIR.PV.Humidity_SP_Prod;
_011: NOP   0;
      U     L     17.0;
      U(    ;
      L     "DB_DRYER_FSHOFF".DRYAIR.PV.Humidity_SP_Prod;
      L     1.000000e+000;
      <R    ;
      )     ;
      SPBNB _012;
      L     1.000000e+000;
      T     "DB_DRYER_FSHOFF".DRYAIR.PV.Humidity_SP_Prod;
_012: NOP   0;
      U     L     17.0;
      U(    ;
      L     "DB_DRYER_FSHOFF".DRYAIR.PV.Humidity_SP_Prod;
      L     6.000000e+001;
      >R    ;
      )     ;
      SPBNB _013;
      L     6.000000e+001;
      T     "DB_DRYER_FSHOFF".DRYAIR.PV.Humidity_SP_Prod;
_013: NOP   0;
NETWORK
TITLE =Trasferimento Dati

// SetPOINT Humidity Dryer System

      L     "EW3790";
      ITD   ;
      DTR   ;
      L     1.000000e+001;
      /R    ;
      T     "DB_DRYER_FSHOFF".DRYAIR.PV.ActHR;
      T     "DB_DRYER_FSHOFF".DRYAIR.HMI_ActProbeHR;

      L     "DB_DRYER_FSHOFF".DRYAIR.PV.Humidity_SP_Prod;
      L     1.000000e+001;
      *R    ;
      RND   ;
      T     "AW3730";

NETWORK
TITLE =

      U     "LOG_1";
      =     L     17.0;
      U     L     17.0;
      UN    "M3040.7";
      SPBNB _014;
      L     0;
      T     "AW3732";
_014: NOP   0;
      U     L     17.0;
      U     "M3040.7";
      SPBNB _015;
      L     1;
      T     "AW3732";
_015: NOP   0;
NETWORK
TITLE =



NETWORK
TITLE =CONTROL/ERROR RELEASE =VALVE VM71

      U     "LOG_1";
      =     L     17.0;
      U     L     17.0;
      U     #RelErrorCR;
      U     #RelErrorCL;
      =     #RelError;
      U     L     17.0;
      U     #RelControlCR;
      U     #RelControlCL;
      U     "SBIT 80FAN73 RUNNING";
      =     #RelControl;
NETWORK
TITLE =FLASH-OFF COOLING VALVE VM71

      U     #RelControl;
      =     L     17.0;
      BLD   103;
      U     #RelError;
      =     L     17.1;
      BLD   103;
      U     "LOG_1";
      =     L     17.2;
      BLD   103;
      CALL "FC_VALVE_MT" (
           REL_CONTROL              := L     17.0,
           RES_ALARM                := L     17.1,
           PBS                      := L     17.2,
           Pos_Valve                := "DBI_PID_FSHOFF_COOL".LMN,
           DDB                      := "DB_GRP_80_R30".VM71_VALVE);
      NOP   0;
NETWORK
TITLE =END



END_FUNCTION

